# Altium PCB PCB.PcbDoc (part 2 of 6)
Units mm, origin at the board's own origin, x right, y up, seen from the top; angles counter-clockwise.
Board outline 101.6 x 101.61 mm, 4 copper layers (Top Layer, GND, POWER, Bottom Layer), stack 1.371 mm thick; 504 components, 345 nets, 1794 pads, 1471 vias.

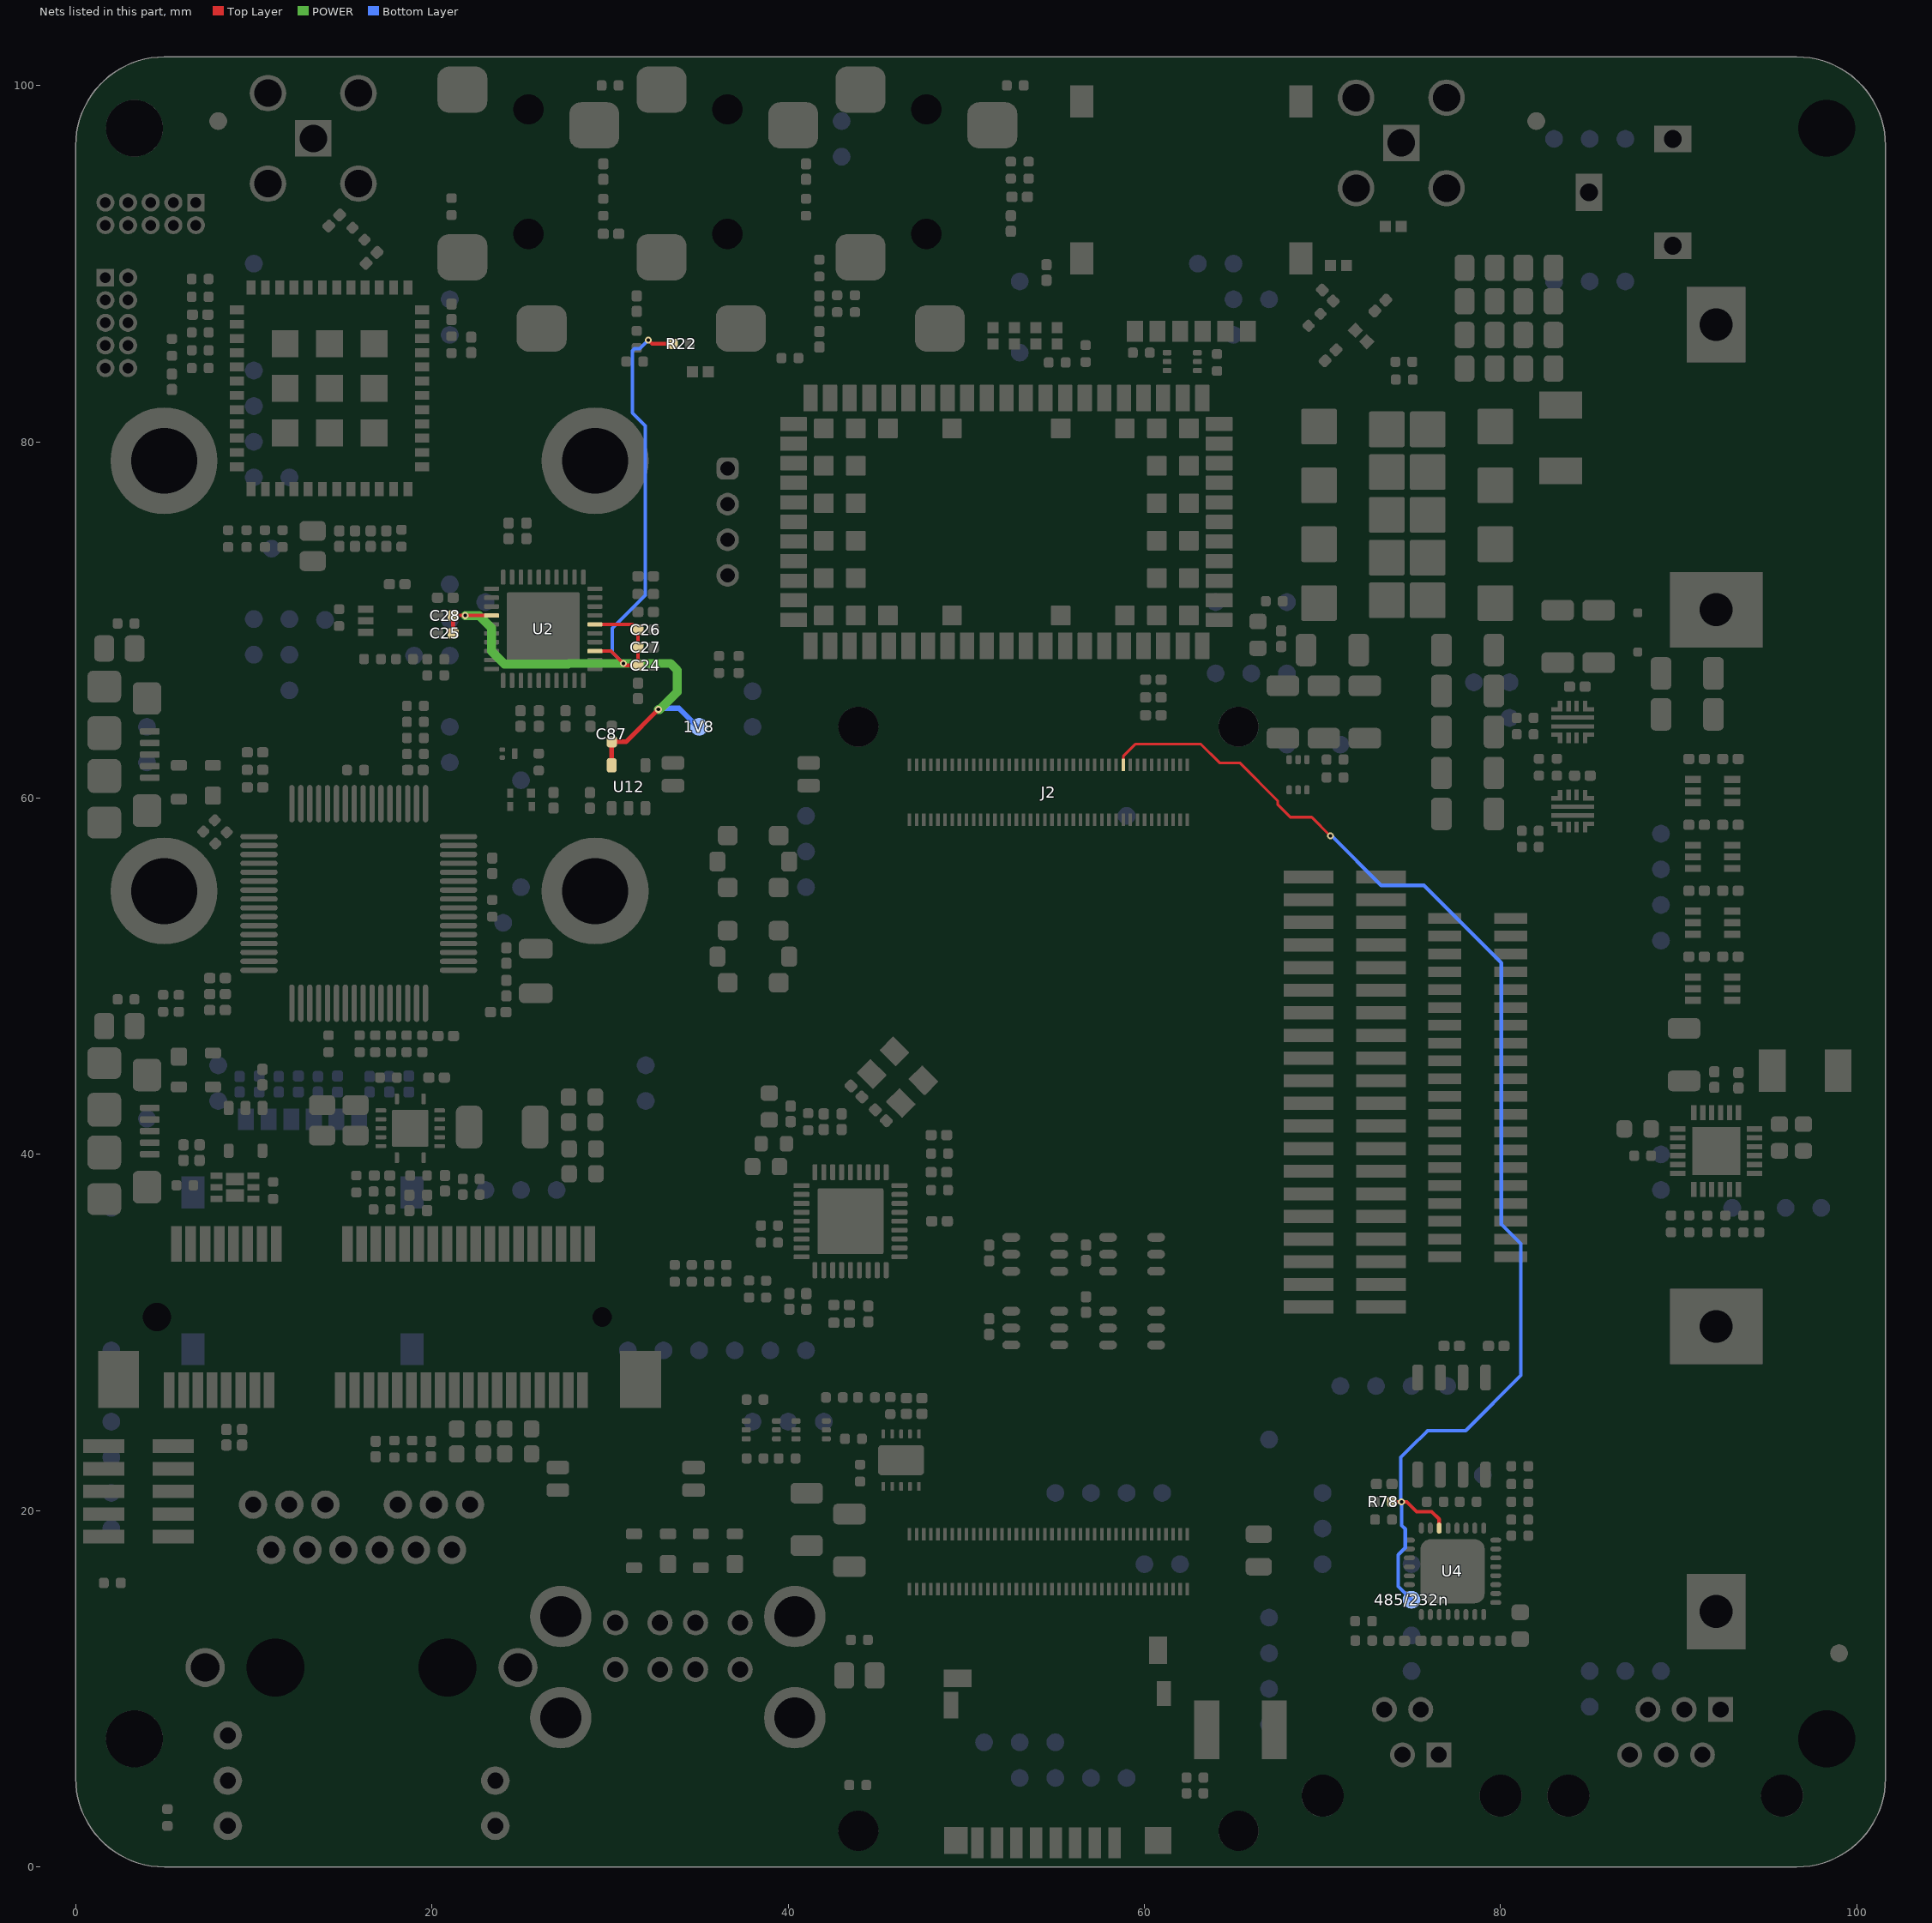
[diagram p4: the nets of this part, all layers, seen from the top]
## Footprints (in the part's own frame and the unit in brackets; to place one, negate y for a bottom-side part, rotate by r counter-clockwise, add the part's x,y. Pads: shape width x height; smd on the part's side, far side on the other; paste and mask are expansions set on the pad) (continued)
0402#3 [mm] "Chip Inductor, 2-Leads, Body  0402 (in) 1005 (mm), IPC Medium Density"
  rect 0.62x0.62 smd mask+0.05: 1(-0.45,0) 2(0.45,0)
  body extent -0.57,-0.27 0.57,0.27, height 0.41
1812 [mm] "Chip Capacitor, Body 4.5x3.2mm, IPC High Density"
  rect 1.4x3.3 smd: 1(-1.9,0) 2(1.9,0)
  body extent -2.4,-1.7 2.4,1.7, height 1.4
1759546-1 [mm]
  rect 0.6x2 smd mask+0: 1(-11.8,-4.25) 2(-11.4,3.95) 3(-11,-4.25) 4(-10.6,3.95) 5(-10.2,-4.25) 6(-9.8,3.95) 7(-9.4,-4.25) 8(-9,3.95) 9(-8.6,-4.25) 10(-8.2,3.95) 11(-7.8,-4.25) 12(-7.4,3.95) 13(-7,-4.25) 14(-6.6,3.95) 15(-6.2,-4.25) 16(-5.8,3.95) 17(-2.2,-4.25) 18(-1.8,3.95) 19(-1.4,-4.25) 20(-1,3.95) 21(-0.6,-4.25) 22(-0.2,3.95) 23(0.2,-4.25) 24(0.6,3.95) 25(1,-4.25) 26(1.4,3.95) 27(1.8,-4.25) 28(2.2,3.95) 29(2.6,-4.25) 30(3,3.95) 31(3.4,-4.25) 32(3.8,3.95) 33(4.2,-4.25) 34(4.6,3.95) 35(5,-4.25) 36(5.4,3.95) 37(5.8,-4.25) 38(6.2,3.95) 39(6.6,-4.25) 40(7,3.95) 41(7.4,-4.25) 42(7.8,3.95) 43(8.2,-4.25) 44(8.6,3.95) 45(9,-4.25) 46(9.4,3.95) 47(9.8,-4.25) 48(10.2,3.95) 49(10.6,-4.25) 50(11,3.95) 51(11.4,-4.25) 52(11.8,3.95)
  round 0 hole 1.6 unplated: MH1(-12.5,-0.15)
  round 0 hole 1.1 unplated: MH2(12.5,-0.15)
  rect 2.3x3.2 smd: MP1(-14.65,-3.65) MP2(14.65,-3.65)
  body extent -15,-4.56 15,4.7, height 9.92
9774070151R [mm]
  round 6 / inner round 4.1 / far side round 4.1 hole 3.7 paste-10 mask+0.1: 1(0,0)
  body extent -2.55,-2.55 2.55,2.55, height 7.03
61400826021 [mm] "USB 2.0 Type A Horizontal Dual Stacked"
  round 1.42 hole 0.92: 1(-3.5,7.11) 2(-1,7.11) 3(1,7.11) 4(3.5,7.11) 5(-3.5,4.49) 6(-1,4.49) 7(1,4.49) 8(3.5,4.49)
  round 3.45 hole 2.3: Shell(-6.57,1.78) Shell(-6.57,7.46) Shell(6.57,1.78) Shell(6.57,7.46)
  body extent -7.91,-8.5 7.91,8.65, height 15.93
615004143821 [mm] "Modular Jack Horizontal Plastic 4P4C Tab Up"
  rect 1.4x1.4 hole 0.9: 1(1.53,1.8)
  round 1.4 hole 0.9: 2(0.51,4.34) 3(-0.51,1.8) 4(-1.53,4.34)
  round 2.36 hole 2.36 unplated: MH1(5,-0.5) MH2(-5,-0.5)
  body extent -6.28,-6.5 6.27,6.5, height 14.55
615006138421 [mm] "Modular Jack Horizontal Plastic 6P6C Tab Up"
  rect 1.4x1.4 hole 0.9: 1(2.55,4.34)
  round 1.4 hole 0.9: 2(1.53,1.8) 3(0.51,4.34) 4(-0.51,1.8) 5(-1.53,4.34) 6(-2.55,1.8)
  round 2.36 hole 2.36 unplated: MH1(-6,-0.5) MH2(6,-0.5)
  body extent -7.19,-6.5 7.19,6.5, height 14.55
ABS07 [mm]
  rrect50% 1.1x1.9 smd: 1(-1.25,0) 2(1.25,0)
  body extent -1.65,-0.83 1.65,0.83, height 0.9
AMPHENOL_114-00841-68 [mm]
  rect 0.7x1.75 smd mask+0.05: 1(3.2,-5.888) 2(2.1,-5.888) 3(1,-5.888) 4(-0.1,-5.888) 5(-1.2,-5.888) 6(-2.3,-5.888) 7(-3.4,-5.888) 8(-4.5,-5.888)
  rect 1x1.55 smd mask+0.05: CD1(5.65,4.912)
  rect 1.55x1 smd mask+0.05: CD2(-5.602,3.337)
  rect 1.3x1.5 smd mask+0: SH1(-5.7,-5.76)
  rect 1.5x1.5 smd mask+0: SH2(5.65,-5.76)
  rect 0.8x1.4 smd mask+0.05: SH3(5.975,2.487)
  rect 0.8x1.5 smd mask+0.05: SH4(-5.975,1.837)
  body extent -6,-10.29 6,4.99, height 1.6
C&K_PTS820_NO_HOLES-1 [mm]
  rrect49% 0.89x1.12 smd: 5(-2.015,0) 6(2.015,0)
  rrect46% 1.11x1.09 smd: PAD(-1.434,-1.46) PAD(-1.434,1.46) PAD(1.434,-1.46) PAD(1.434,1.46)
  body extent -2.25,-1.45 2.25,1.45, height 2
CAP-0402#1 [mm] "Chip Capacitor, 2-Leads, Body  0402 (in) 1005 (mm), IPC Medium Density"
  rrect52% 0.63x0.58 smd: 1(-0.435,0) 2(0.435,0)
  body extent -0.5,-0.25 0.5,0.25, height 0.5
CAP-0402#2 [mm] "Chip Capacitor, 2-Leads, Body  0402 (in) 1005 (mm), IPC Medium Density"
  rrect52% 0.63x0.58 smd mask+0: 1(-0.435,0) 2(0.435,0)
  body extent -0.5,-0.25 0.5,0.25, height 0.5
CAP-0603#1 [mm] "Chip Capacitor, Body 0603 imperial,1.6x0.8mm, IPC High Density"
  rrect51% 0.87x0.97 smd: 1(-0.75,0) 2(0.75,0)
  body extent -0.8,-0.4 0.8,0.4, height 0.8
CAP-0603#2 [mm] "Chip Capacitor, Body 0603 imperial,1.6x0.8mm, IPC High Density"
  rrect51% 0.87x0.97 smd mask+0: 1(-0.75,0) 2(0.75,0)
  body extent -0.8,-0.4 0.8,0.4, height 0.8
CAP-0805#1 [mm] "Chip Capacitor, Body 0805 imperial, 2.0x1.2mm, IPC Medium Density"
  rrect45% 1.11x1.47 smd: 1(-0.85,0) 2(0.85,0)
  body extent -1,-0.62 1,0.63, height 1.25
CAP-0805#2 [mm] "Chip Capacitor, Body 0805 imperial, 2.0x1.2mm, IPC Medium Density"
  rrect45% 1.11x1.47 smd mask+0: 1(-0.85,0) 2(0.85,0)
  body extent -1,-0.62 1,0.63, height 1.25
CAP-1206#1 [mm] "Chip Capacitor, 2-Leads, 1206 (in) 3216 (mm), IPC Medium Density"
  rrect43% 1.16x1.82 smd: 1(-1.475,0) 2(1.475,0)
  body extent -1.6,-0.8 1.6,0.8, height 1.6
CAP-1206#2 [mm] "Chip Capacitor, 2-Leads, 1206 (in) 3216 (mm), IPC Medium Density"
  rrect43% 1.16x1.82 smd mask+0: 1(-1.475,0) 2(1.475,0)
  body extent -1.6,-0.8 1.6,0.8, height 1.6
CMWX1ZZABZ [mil]
  rect 31.5x19.69 smd mask+2.76: 1(-222.44,173.23) 2(-222.44,141.73) 3(-222.44,110.24) 4(-222.44,78.74) 5(-222.44,47.24) 6(-222.44,15.75) 7(-222.44,-15.75) 8(-222.44,-47.24) 9(-222.44,-78.74) 10(-222.44,-110.24) 11(-222.44,-141.73) 12(-222.44,-173.23) 25(222.44,-173.23) 26(222.44,-141.73) 27(222.44,-110.24) 28(222.44,-78.74) 29(222.44,-47.24) 30(222.44,-15.75) 31(222.44,15.75) 32(222.44,47.24) 33(222.44,78.74) 34(222.44,110.24) 35(222.44,141.73) 36(222.44,173.23)
  rect 19.69x31.5 smd mask+2.76: 13(-173.23,-204.72) 14(-141.73,-204.72) 15(-110.24,-204.72) 16(-78.74,-204.72) 17(-47.24,-204.72) 18(-15.75,-204.72) 19(15.75,-204.72) 20(47.24,-204.72) 21(78.74,-204.72) 22(110.24,-204.72) 23(141.73,-204.72) 24(173.23,-204.72) 37(173.23,204.72) 38(141.73,204.72) 39(110.24,204.72) 40(78.74,204.72) 41(47.24,204.72) 42(15.75,204.72) 43(-15.75,204.72) 44(-47.24,204.72) 45(-78.74,204.72) 46(-110.24,204.72) 47(-141.73,204.72) 48(-173.23,204.72)
  rect 59.06x59.06 smd mask+2.76: 49(-98.43,98.43) 50(0,98.43) 51(98.43,98.43) 52(-98.43,0) 53(0,0) 54(98.43,0) 55(-98.43,-98.43) 56(0,-98.43) 57(98.43,-98.43)
  body extent -244,-225 248,231, height 69
CRYSTAL3.2X2.5 [mm]
  rrect10% 1.3x1.1 smd: 1(-1.15,-0.9) 2(1.15,-0.9) 3(1.15,0.9) 4(-1.15,0.9)
  body extent -1.65,-1.14 1.52,1.27, height 0.6
CTS-218-2LPST_V [mm] "SMD, 4-Leads, Body 5.8x3.71mm, Pitch 1.27mm"
  rrect50% 1.27x0.76 smd: 1(-3.81,0.635) 2(-3.81,-0.635) 3(3.81,-0.635) 4(3.81,0.635)
  body extent -2.9,-1.86 2.9,1.86, height 2.65
CUI-PJ-102A_V [mm] "THD, 3-Leads, Body 14.4x9mm, Pitch 3mm"
  rect 2.1x1.5 hole 1 square: 1(0.2,-6.5) 2(0.2,-0.5)
  rect 1.5x2.1 hole 1 square: 3(-4.5,-3.5)
  body extent -4.7,-7.2 4.7,7.2, height 11.5
DF40HC(3.5)-80DS-0.4V(51)-Footprint-1 [mm]
  rect 0.2x0.7 smd: 1(-7.8,1.54) 2(-7.8,-1.54) 3(-7.4,1.54) 4(-7.4,-1.54) 5(-7,1.54) 6(-7,-1.54) 7(-6.6,1.54) 8(-6.6,-1.54) 9(-6.2,1.54) 10(-6.2,-1.54) 11(-5.8,1.54) 12(-5.8,-1.54) 13(-5.4,1.54) 14(-5.4,-1.54) 15(-5,1.54) 16(-5,-1.54) 17(-4.6,1.54) 18(-4.6,-1.54) 19(-4.2,1.54) 20(-4.2,-1.54) 21(-3.8,1.54) 22(-3.8,-1.54) 23(-3.4,1.54) 24(-3.4,-1.54) 25(-3,1.54) 26(-3,-1.54) 27(-2.6,1.54) 28(-2.6,-1.54) 29(-2.2,1.54) 30(-2.2,-1.54) 31(-1.8,1.54) 32(-1.8,-1.54) 33(-1.4,1.54) 34(-1.4,-1.54) 35(-1,1.54) 36(-1,-1.54) 37(-0.6,1.54) 38(-0.6,-1.54) 39(-0.2,1.54) 40(-0.2,-1.54) 41(0.2,1.54) 42(0.2,-1.54) 43(0.6,1.54) 44(0.6,-1.54) 45(1,1.54) 46(1,-1.54) 47(1.4,1.54) 48(1.4,-1.54) 49(1.8,1.54) 50(1.8,-1.54) 51(2.2,1.54) 52(2.2,-1.54) 53(2.6,1.54) 54(2.6,-1.54) 55(3,1.54) 56(3,-1.54) 57(3.4,1.54) 58(3.4,-1.54) 59(3.8,1.54) 60(3.8,-1.54) 61(4.2,1.54) 62(4.2,-1.54) 63(4.6,1.54) 64(4.6,-1.54) 65(5,1.54) 66(5,-1.54) 67(5.4,1.54) 68(5.4,-1.54) 69(5.8,1.54) 70(5.8,-1.54) 71(6.2,1.54) 72(6.2,-1.54) 73(6.6,1.54) 74(6.6,-1.54) 75(7,1.54) 76(7,-1.54) 77(7.4,1.54) 78(7.4,-1.54) 79(7.8,1.54) 80(7.8,-1.54)
  body extent -9.32,-1.69 9.28,1.69, height 3.4
DFN120P120X89-4M [mm] "DFN, 4-Leads, Body 1,60x1,20mm, Pitch 1,20mm, IPC Low Density"
  rect 0.45x0.5 smd mask+0.04: 1(-0.555,-0.375)
  rect 0.35x0.5 smd mask+0.04: 2(0.605,-0.375) 3(0.605,0.375) 4(-0.605,0.375)
  body extent -0.8,-0.6 0.8,0.6, height 0.9
"Fiducial mark 1mm with circle-Footprint-1" [mm]
  round 1 smd paste-10 mask+0.5: 1(0,0)
  Top Layer pour cut-out: 0,1 0.383,0.924 0.707,0.707 0.924,0.383 1,0 1,0 0.924,-0.383 0.707,-0.707 0.383,-0.924 0,-1 0,-1 -0.383,-0.924 -0.707,-0.707 -0.924,-0.383 -1,0 -1,0 -0.924,0.383 -0.707,0.707 -0.383,0.924 0,1
FTSH-105-01-F-DV-Footprint-1 [mm]
  rect 0.76x2.3 smd: 1(-2.54,-1.95) 2(-2.54,1.95) 3(-1.27,-1.95) 4(-1.27,1.95) 5(0,-1.95) 6(0,1.95) 7(1.27,-1.95) 8(1.27,1.95) 9(2.54,-1.95) 10(2.54,1.95)
  body extent -3.17,-2.92 3.17,2.92, height 5.98
FW-20-05-G-D-254-150-Footprint-1 [mil]
  rect 110x29 smd: 1(-80,475) 2(80,475) 3(-80,425) 4(80,425) 5(-80,375) 6(80,375) 7(-80,325) 8(80,325) 9(-80,275) 10(80,275) 11(-80,225) 12(80,225) 13(-80,175) 14(80,175) 15(-80,125) 16(80,125) 17(-80,75) 18(80,75) 19(-80,25) 20(80,25) 21(-80,-25) 22(80,-25) 23(-80,-75) 24(80,-75) 25(-80,-125) 26(80,-125) 27(-80,-175) 28(80,-175) 29(-80,-225) 30(80,-225) 31(-80,-275) 32(80,-275) 33(-80,-325) 34(80,-325) 35(-80,-375) 36(80,-375) 37(-80,-425) 38(80,-425) 39(-80,-475) 40(80,-475)
  body extent -115,-500 115,500, height 388
HW4-2.0 [mm]
  rrect50% 1.23x1.23 hole 0.8: 1(-3,0)
  round 1.27 / inner round 1.524 / far side round 1.27 hole 0.8: 2(-1,0) 3(1,0) 4(3,0)
  body extent -5.02,-3.22 5.02,2.03, height 8.09
L-0603 [mm] "Chip Inductor - Body 0603 imperial,1.6x0.8mm, IPC High Density"
  rrect51% 0.75x0.87 smd: 1(-0.71,0) 2(0.71,0)
  body extent -0.8,-0.4 0.8,0.4, height 0.8
LGA18C100P6X4_1200X1200X360 [mm] "LGA, 18-Leads, Body 12.00x12.00mmx3.60mm, Pitch 1.00mm"
  rrect10% 2x2 smd: 1(-4.95,4.95) 2(-4.95,1.65) 3(-4.95,-1.65) 4(-4.95,-4.95) 5(4.95,-4.95) 8(4.95,4.95) GND(-1.15,-4.8) GND(-1.15,-2.4) GND(-1.15,0) GND(-1.15,2.4) GND(-1.15,4.8) GND(1.15,-4.8) GND(1.15,-2.4) GND(1.15,0) GND(1.15,2.4) GND(1.15,4.8) GND(4.95,-1.65) GND(4.95,1.65)
  body extent -6.05,-6.05 6.05,6.05, height 3.6
MCHP-QFN-36_V [mm] "QFN, 36-Leads, Body 6.00x6.00mm, Pitch 0.50mm, Thermal Pad 3.70x3.70mm"
  rrect50% 0.9x0.28 smd mask+0.03: 1(-2.75,2) 2(-2.75,1.5) 3(-2.75,1) 4(-2.75,0.5) 5(-2.75,0) 6(-2.75,-0.5) 7(-2.75,-1) 8(-2.75,-1.5) 9(-2.75,-2) 19(2.75,-2) 20(2.75,-1.5) 21(2.75,-1) 22(2.75,-0.5) 23(2.75,0) 24(2.75,0.5) 25(2.75,1) 26(2.75,1.5) 27(2.75,2)
  rrect50% 0.28x0.9 smd mask+0.03: 10(-2,-2.75) 11(-1.5,-2.75) 12(-1,-2.75) 13(-0.5,-2.75) 14(0,-2.75) 15(0.5,-2.75) 16(1,-2.75) 17(1.5,-2.75) 18(2,-2.75) 28(2,2.75) 29(1.5,2.75) 30(1,2.75) 31(0.5,2.75) 32(0,2.75) 33(-0.5,2.75) 34(-1,2.75) 35(-1.5,2.75) 36(-2,2.75)
  rrect5% 3.7x3.7 smd paste-4 mask+0.03: 37(0,0)
  body extent -3.05,-3.05 3.05,3.05, height 1
MOLX-731000114_V [mm] "Connector, 5-Leads, Body 14.8x6.35mm, Pitch 2.54mm"
  rect 2.05x2.05 hole 1.54: 1(0,0)
  round 2.05 hole 1.54: 2(-2.54,2.54) 3(-2.54,-2.54) 4(2.54,-2.54) 5(2.54,2.54)
  body extent -11.62,-3.17 3.18,3.18, height 9.57
PINHEAD_2X05_127 [mil]
  rect 38.73x38.73 / inner rect 38.74x38.74 / far side rect 38.73x38.73 hole 23.62: 1(-25,100)
  round 40 hole 23.62: 2(25,100) 3(-25,50) 4(25,50) 5(-25,0) 6(25,0) 7(-25,-50) 8(25,-50) 9(-25,-100) 10(25,-100)
PQFN50P300X300X55_HS-21L [mm] "PQFN, 20-Leads, Body 3.00x3.00mm, Pitch 0.50mm, Thermal Pad 1.69x2.59mm, IPC High Density"
  rrect50% 0.2x0.5 smd: 1(-1,-1.475) 2(-0.5,-1.475) 3(0,-1.475) 4(0.5,-1.475) 5(1,-1.475) 6(1,1.475) 7(0.5,1.475) 8(0,1.475) 9(-0.5,1.475) 10(-1,1.475)
  rrect25% 2.59x1.69 smd: 11(0,0)
  body extent -1.5,-1.5 1.5,1.5, height 0.55
QFN50P200X200X100-16N [mm] "QFN, 16-Leads, Body 2,00x2,00mm, Pitch 0,50mm, IPC Medium Density"
  rect 0.6x0.25 smd mask+0.03: 1(-0.889,0.7) 2(-0.9,0.225) 3(-0.9,-0.225) 4(-0.889,-0.7) 7(0.889,-0.7) 8(0.9,-0.225) 9(0.9,0.225) 10(0.889,0.7)
  rect 0.25x0.6 smd mask+0.03: 1(-0.714,0.9) 4(-0.714,-0.9) 7(0.714,-0.9) 10(0.714,0.9)
  rect 0.25x2.4 smd mask+0.03: 5(-0.25,0) 6(0.25,0)
  body extent -1.05,-1.05 1.05,1.05, height 1
QFN50P500X500X100_HS-33N [mm] "QFN, 32-Leads, Body 5,00x5,00mm, Pitch 0,50mm, Thermal Pad 3,65x3,65mm, IPC Medium Density"
  oval 0.625x0.275 smd: 1(-2.425,1.75) 2(-2.425,1.25) 3(-2.425,0.75) 4(-2.425,0.25) 5(-2.425,-0.25) 6(-2.425,-0.75) 7(-2.425,-1.25) 8(-2.425,-1.75) 17(2.425,-1.75) 18(2.425,-1.25) 19(2.425,-0.75) 20(2.425,-0.25) 21(2.425,0.25) 22(2.425,0.75) 23(2.425,1.25) 24(2.425,1.75)
  oval 0.275x0.625 smd: 9(-1.75,-2.425) 10(-1.25,-2.425) 11(-0.75,-2.425) 12(-0.25,-2.425) 13(0.25,-2.425) 14(0.75,-2.425) 15(1.25,-2.425) 16(1.75,-2.425) 25(1.75,2.425) 26(1.25,2.425) 27(0.75,2.425) 28(0.25,2.425) 29(-0.25,2.425) 30(-0.75,2.425) 31(-1.25,2.425) 32(-1.75,2.425)
  rrect30% 3.6x3.6 smd paste-6: 33(0,0)
  body extent -2.5,-2.5 2.5,2.5, height 1.02
QFN127P600-8N [mm]
  rrect50% 0.85x0.25 smd mask+0.05: 1(-2.9,2.25) 2(-2.9,1.75) 3(-2.9,1.25) 4(-2.9,0.75) 5(-2.9,0.25) 6(-2.9,-0.25) 7(-2.9,-0.75) 8(-2.9,-1.25) 9(-2.9,-1.75) 10(-2.9,-2.25) 21(2.9,-2.25) 22(2.9,-1.75) 23(2.9,-1.25) 24(2.9,-0.75) 25(2.9,-0.25) 26(2.9,0.25) 27(2.9,0.75) 28(2.9,1.25) 29(2.9,1.75) 30(2.9,2.25)
  rrect50% 0.25x0.85 smd mask+0.05: 11(-2.25,-2.9) 12(-1.75,-2.9) 13(-1.25,-2.9) 14(-0.75,-2.9) 15(-0.25,-2.9) 16(0.25,-2.9) 17(0.75,-2.9) 18(1.25,-2.9) 19(1.75,-2.9) 20(2.25,-2.9) 31(2.25,2.9) 32(1.75,2.9) 33(1.25,2.9) 34(0.75,2.9) 35(0.25,2.9) 36(-0.25,2.9) 37(-0.75,2.9) 38(-1.25,2.9) 39(-1.75,2.9) 40(-2.25,2.9)
  rrect5% 4.1x4.1 smd paste-5 mask+0.05: 41(0,0)
  body extent -3,-3 3,3, height 1
RES-0402#1 [mm] "Chip Resistor, 2-Leads, Body  0402 (in) 1005 (mm), IPC Medium Density"
  rrect51% 0.55x0.58 smd: 1(-0.475,0) 2(0.475,0)
  body extent -0.5,-0.25 0.5,0.25, height 0.34
RES-0402#2 [mm] "Chip Resistor, 2-Leads, Body  0402 (in) 1005 (mm), IPC Medium Density"
  rrect51% 0.55x0.58 smd mask+0: 1(-0.475,0) 2(0.475,0)
  body extent -0.5,-0.25 0.5,0.25, height 0.34
RES-0402#3 [mm] "Chip Resistor, 2-Leads, Body  0402 (in) 1005 (mm), IPC Medium Density"
  rrect51% 0.55x0.58 smd mask+0: 1(-0.475,0)
  rrect51% 0.55x0.58 smd: 2(0.475,0)
  body extent -0.5,-0.25 0.5,0.25, height 0.34
RES-0805 [mm] "Chip Resistor - Body 0805 imperial, 2.0x1.2mm, IPC Medium Density"
  rrect51% 0.99x1.47 smd paste-1.47: 1(-0.915,0) 2(0.915,0)
  body extent -1,-0.62 1,0.63, height 0.58
RHL0014A_V [mm] "QFN, 14-Leads, Body 3.5x3.5mm, Pitch 0.5mm, Thermal Pad 2.05x2.05mm, TI Recommended"
  rrect42% 0.24x0.6 smd: 1(-0.75,1.65) 7(-0.75,-1.65) 8(0.75,-1.65) 14(0.75,1.65)
  rrect42% 0.6x0.24 smd: 2(-1.65,1) 3(-1.65,0.5) 4(-1.65,0) 5(-1.65,-0.5) 6(-1.65,-1) 9(1.65,-1) 10(1.65,-0.5) 11(1.65,0) 12(1.65,0.5) 13(1.65,1)
  rrect5% 2.05x2.05 smd paste-1.025: 15(0,0)
  Top Layer region: -0.375,0.762 0.375,0.762 0.375,1.75 0.175,1.75 0.175,1.425 -0.175,1.425 -0.175,1.75 -0.375,1.75
  Top Layer region: -0.375,0 0.375,0 0.375,-1.75 0.175,-1.75 0.175,-1.425 -0.175,-1.425 -0.175,-1.75 -0.375,-1.75
  body extent -1.68,-1.83 1.68,1.82, height 1
SARA-96 [mil]
  rrect10% 31.5x59.06 smd: 1(-433.07,-273.62) 2(-389.76,-273.62) 3(-346.46,-273.62) 4(-303.15,-273.62) 5(-259.84,-273.62) 6(-216.54,-273.62) 7(-173.23,-273.62) 8(-129.92,-273.62) 9(-86.61,-273.62) 10(-43.31,-273.62) 11(0,-273.62) 12(43.31,-273.62) 13(86.61,-273.62) 14(129.92,-273.62) 15(173.23,-273.62) 16(216.54,-273.62) 17(259.84,-273.62) 18(303.15,-273.62) 19(346.46,-273.62) 20(389.76,-273.62) 21(433.07,-273.62) 33(433.07,273.62) 34(389.76,273.62) 35(346.46,273.62) 36(303.15,273.62) 37(259.84,273.62) 38(216.54,273.62) 39(173.23,273.62) 40(129.92,273.62) 41(86.61,273.62) 42(43.31,273.62) 43(0,273.62) 44(-43.31,273.62) 45(-86.61,273.62) 46(-129.92,273.62) 47(-173.23,273.62) 48(-216.54,273.62) 49(-259.84,273.62) 50(-303.15,273.62) 51(-346.46,273.62) 52(-389.76,273.62) 53(-433.07,273.62)
  rrect10% 59.06x31.5 smd: 22(470.47,-216.54) 23(470.47,-173.23) 24(470.47,-129.92) 25(470.47,-86.61) 26(470.47,-43.31) 27(470.47,0) 28(470.47,43.31) 29(470.47,86.61) 30(470.47,129.92) 31(470.47,173.23) 32(470.47,216.54) 54(-470.47,216.54) 55(-470.47,173.23) 56(-470.47,129.92) 57(-470.47,86.61) 58(-470.47,43.31) 59(-470.47,0) 60(-470.47,-43.31) 61(-470.47,-86.61) 62(-470.47,-129.92) 63(-470.47,-173.23) 64(-470.47,-216.54)
  rrect10% 43.31x43.31 smd: 65(-403.54,-206.69) 66(-403.54,-124.02) 67(-403.54,-41.34) 68(-403.54,41.34) 69(-403.54,124.02) 70(-403.54,206.69) 71(-332.68,-206.69) 72(-332.68,-124.02) 73(-332.68,-41.34) 74(-332.68,41.34) 75(-332.68,124.02) 76(-332.68,206.69) 77(-261.81,-206.69) 78(-261.81,206.69) 79(-120.08,-206.69) 80(-120.08,206.69) 81(120.08,-206.69) 82(120.08,206.69) 83(261.81,-206.69) 84(261.81,206.69) 85(332.68,-206.69) 86(332.68,-124.02) 87(332.68,-41.34) 88(332.68,41.34) 89(332.68,124.02) 90(332.68,206.69) 91(403.54,-206.69) 92(403.54,-124.02) 93(403.54,-41.34) 94(403.54,41.34) 95(403.54,124.02) 96(403.54,206.69)
  body extent -512,-315 512,315, height 103
SC70-5 [mm] "SC70-5/SOT353, 5-Leads, Body 2.00x2.10mm, Pitch 0.65mm, IPC Medium Density"
  rect 0.85x0.4 smd mask+0.05: 1(-1.1,0.65) 2(-1.1,0) 3(-1.1,-0.65) 4(1.1,-0.65) 5(1.1,0.65)
  body extent -1.2,-1.08 1.2,1.08, height 1.1
sc70-6 [mm]
  rrect10% 0.9x0.4 smd mask+0.05: 1(-1.1,0.65) 2(-1.1,0) 3(-1.1,-0.65) 4(1.1,-0.65) 5(1.1,0) 6(1.1,0.65)
  body extent -1.05,-1 1.05,1, height 0.93
SIM8060-6-0-14-00-A-Footprint-1 [mm]
  rect 0.9x1.2 smd: C1(-3.17,7.32) C2(-0.63,7.32) C3(1.91,7.32) C5(-1.9,7.32) C6(0.64,7.32) C7(3.18,7.32)
  rect 1.3x1.8 smd: G1(-6.15,3.22) G2(6.15,3.22) G3(-6.15,-5.58) G4(6.15,-5.58)
  silkscreen extent -3.3,8.2 -3.1,8.4, body extent -6.67,-7.92 6.67,7.83, height 1.53
SJ-3524-SMT-TR-Footprint-1 [mm]
  rrect50% 2.6x2.8 smd: 1(-4.59,-3.7) 2(-2.59,3.7) 3(4.81,-3.7) 4(8.81,0.75)
  round 0 hole 1.7 unplated: MH1(-3.49,0) MH2(3.51,0)
  body extent -9.49,-4.5 9.51,4.5, height 5.1
SOD323 [mm] "Molded Diode, 2-Leads, Body 1,70x1,25mm, IPC High Density"
  rrect50% 0.5x0.5 smd: 1(-1.1,0) 2(1.1,0)
  body extent -1.12,-0.67 1.12,0.67, height 1.1
SON65P205X205X75-8N-MWSD [mm]
  rect 0.37x0.67 smd mask+0.025: A(0.65,1.04) D(-0.65,1.04) G(0,-1.04) K(0.65,-1.04) NC(0,1.04) S(-0.65,-1.04)
  rect 0.7x1 smd mask+0.025: D2(-0.467,0) K2(0.467,0)
  body extent -1,-1 1,1, height 0.75
SOT25 [mil]
  rrect50% 21.65x31.5 smd: 1(-37.4,-47.24) 2(0,-47.24) 3(37.4,-47.24) 4(37.4,47.24) 5(-37.4,47.24)
  body extent -59,-44 59,50, height 43
SOT190P230X110-4N [mm]
  rrect33% 1.01x0.91 smd paste+0 mask+0: 1(-0.75,-0.955)
  rrect49% 0.61x0.91 smd paste+0 mask+0: 2(0.95,-0.955) 3(0.95,0.955) 4(-0.95,0.955)
  body extent -1.45,-1.15 1.45,1.15, height 1
SOT883 [mm]
  rrect50% 0.3x0.25 smd mask+0: 1(-0.35,-0.225) 2(-0.35,0.225)
  rrect25% 0.3x0.6 smd mask+0.05: 3(0.35,0)
  body extent -0.51,-0.31 0.51,0.31, height 0.5
SOTFL50P158X60-6N [mm] "SOTFL, 6-Leads, Body 1,55x1,58mm, Pitch 0,50mm, IPC Medium Density"
  rrect50% 0.5x0.3 smd mask+0.025: 1(-0.85,0.5) 2(-0.85,0) 3(-0.85,-0.5) 4(0.85,-0.5) 5(0.85,0) 6(0.85,0.5)
  body extent -0.79,-0.8 0.79,0.8, height 0.6
SRP4020#1 [mm]
  rect 1.5x2.4 smd: 1(-1.85,0) 2(1.85,0)
  body extent -2.15,-2 2.15,2, height 1.9
SRP4020#2 [mm]
  rrect50% 1.5x2.4 smd: 1(-1.85,0) 2(1.85,0)
  body extent -2.7,-2.25 2.7,2.25, height 0.25
STM-LQFP64_M [mm] "Thin QFP, 64-Leads, Body 10x10mm, Pitch 0.5mm, IPC Low Density"
  oval 2.1x0.3 smd: 1(-5.6,3.75) 2(-5.6,3.25) 3(-5.6,2.75) 4(-5.6,2.25) 5(-5.6,1.75) 6(-5.6,1.25) 7(-5.6,0.75) 8(-5.6,0.25) 9(-5.6,-0.25) 10(-5.6,-0.75) 11(-5.6,-1.25) 12(-5.6,-1.75) 13(-5.6,-2.25) 14(-5.6,-2.75) 15(-5.6,-3.25) 16(-5.6,-3.75) 33(5.6,-3.75) 34(5.6,-3.25) 35(5.6,-2.75) 36(5.6,-2.25) 37(5.6,-1.75) 38(5.6,-1.25) 39(5.6,-0.75) 40(5.6,-0.25) 41(5.6,0.25) 42(5.6,0.75) 43(5.6,1.25) 44(5.6,1.75) 45(5.6,2.25) 46(5.6,2.75) 47(5.6,3.25) 48(5.6,3.75)
  oval 0.3x2.1 smd: 17(-3.75,-5.6) 18(-3.25,-5.6) 19(-2.75,-5.6) 20(-2.25,-5.6) 21(-1.75,-5.6) 22(-1.25,-5.6) 23(-0.75,-5.6) 24(-0.25,-5.6) 25(0.25,-5.6) 26(0.75,-5.6) 27(1.25,-5.6) 28(1.75,-5.6) 29(2.25,-5.6) 30(2.75,-5.6) 31(3.25,-5.6) 32(3.75,-5.6) 49(3.75,5.6) 50(3.25,5.6) 51(2.75,5.6) 52(2.25,5.6) 53(1.75,5.6) 54(1.25,5.6) 55(0.75,5.6) 56(0.25,5.6) 57(-0.25,5.6) 58(-0.75,5.6) 59(-1.25,5.6) 60(-1.75,5.6) 61(-2.25,5.6) 62(-2.75,5.6) 63(-3.25,5.6) 64(-3.75,5.6)
  body extent -6,-6 6,6, height 1.6
TJA1049T_3J-Footprint-1 [mm]
  rrect50% 1.45x0.6 smd: 1(-2.725,1.905) 2(-2.725,0.635) 3(-2.725,-0.635) 4(-2.725,-1.905) 5(2.725,-1.905) 6(2.725,-0.635) 7(2.725,0.635) 8(2.725,1.905)
  silkscreen extent -1.14,1.53 -0.89,1.78, body extent -3,-2.5 3,2.5, height 1.75
TP-1.00MM#1 [mm]
  rrect100% 1x1 smd paste-2.54: X(0,0)
TP-1.00MM#2 [mm]
  rrect100% 1x1 smd paste-2.54: X(0.486,0)
TP-1.00MM#3 [mm]
  rrect100% 1x1 smd paste-2.54: X(-0.051,0.686)
TP-1.00MM#4 [mm]
  rrect100% 1x1 smd paste-2.54: X(0,-0.588)
TP-1.00MM#5 [mm]
  rrect100% 1x1 smd paste-2.54: X(-0.711,-1.041)
TP-1.00MM#6 [mm]
  rrect100% 1x1 smd paste-2.54: X(-1.168,-6.533)
TP-1.00MM#7 [mm]
  rrect100% 1x1 smd paste-2.54: X(0.813,-7.379)
TP-1.00MM#8 [mm]
  rrect100% 1x1 smd paste-2.54: X(0,-8.395)
TP-1.00MM#9 [mm]
  rrect100% 1x1 smd paste-2.54: X(0,1.27)
"TRJK0071AWNL -Footprint-2" [mm]
  round 1.6 hole 0.9: 1(5.075,0) 2(3.045,0) 3(1.015,0) 4(-1.015,0) 5(-3.045,0) 6(-5.075,0) 7(6.09,2.54) 8(4.06,2.54) 9(2.03,2.54) 10(-2.03,2.54) 11(-4.06,2.54) 12(-6.09,2.54) 13(7.51,-12.95) 14(7.51,-15.49) 15(-7.51,-10.41) 16(-7.51,-12.95) 17(-7.51,-15.49)
  round 2.2 hole 1.6: SH1(-8.78,-6.6) SH2(8.78,-6.6)
  round 0 hole 3.25 unplated: SHNP1(-4.825,-6.6) SHNP2(4.825,-6.6)
  body extent -10.45,-19.78 10.5,4.35, height 12.89
TSOP95P280X110-6N [mm] "TSOP, 6-Leads, Body 2,90x1,50mm, Pitch 0,95mm, IPC Medium Density"
  oval 1x0.5 smd: 1(-1.35,0.95) 2(-1.35,0) 3(-1.35,-0.95) 4(1.35,-0.95) 5(1.35,0) 6(1.35,0.95)
  body extent -1.5,-1.55 1.5,1.55, height 1.1
VQFN24 [mm]
  rect 0.3x0.85 smd mask+0.02: 1(1.25,2.155) 2(0.75,2.155) 3(0.25,2.155) 4(-0.25,2.155) 5(-0.75,2.155) 6(-1.25,2.155) 13(-1.25,-2.155) 14(-0.75,-2.155) 15(-0.25,-2.155) 16(0.25,-2.155) 17(0.75,-2.155) 18(1.25,-2.155)
  rect 0.85x0.3 smd mask+0.02: 7(-2.155,1.25) 8(-2.155,0.75) 9(-2.155,0.25) 10(-2.155,-0.25) 11(-2.155,-0.75) 12(-2.155,-1.25) 19(2.155,-1.25) 20(2.155,-0.75) 21(2.155,-0.25) 22(2.155,0.25) 23(2.155,0.75) 24(2.155,1.25)
  rect 2.7x2.7 smd paste-5 mask+0.05: EXP(0,0)
  silkscreen extent 1.95,1.98 2.15,2.18, body extent -2.05,-2.05 2.05,2.05, height 1
ZX62-AB-5PA#1 [mm]
  rrect49% 0.37x1.11 smd paste+0 mask+0: 1(-1.3,2.56) 2(-0.65,2.56) 3(0,2.56) 4(0.65,2.56) 5(1.3,2.56)
  rrect37% 1.825x1.6 smd paste+0 mask+0: M1(-3.147,2.4) M4(3.147,2.4)
  rrect37% 1.78x1.9 smd paste+0 mask+0: M2(-3.82,0) M3(3.82,0)
  rrect37% 1.9x1.9 smd paste+0 mask+0: M5(-1.2,0) M6(1.2,0)
  body extent -4.4,-2.75 4.4,2.85, height 2.75
ZX62-AB-5PA#2 [mm]
  rrect49% 0.37x1.11 smd paste+0: 1(-1.3,2.56) 2(-0.65,2.56) 3(0,2.56)
  rrect49% 0.37x1.11 smd: 4(0.65,2.56) 5(1.3,2.56)
  rrect37% 1.825x1.6 smd paste+0: M1(-3.148,2.4) M4(3.148,2.4)
  rrect37% 1.78x1.9 smd paste+0: M2(-3.82,0) M3(3.82,0)
  rrect37% 1.9x1.9 smd paste+0: M5(-1.2,0) M6(1.2,0)
  body extent -4.4,-2.75 4.4,2.85, height 2.75

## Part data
1V8 3V3_1 3V3_2 3V3_DBG 3V3_PCIE 3V3_PCIE_1 3V3_PCIE_2 3V8 3V8_2 3V8_3 5V 5V_1 5V_2 12MHz_CLK 485/232n A AUDIO_MCLK AUDIO_RST B BAT BAT_GND CAN0_RX CAN0_TX CAN1_RX CAN1_TX CANH CANL CS_AIN2A CS_AIN2B CS_AIN3A CS_AIN3B DBG_3V3 DBG_BOOT DBG_GND DBG_SWCLK DBG_SWDIO DGB_RST EN_485 EN_CAN ETH_L1 ETH_L2 GND_3V3_1 GND_3V3_2 GND_3V8_1 GND_3V8_2 GND_3V8_3 H/Fn HUB_EN0 HUB_EN1 HUB_EN2 HUB_SCL HUB_SDA I2C1_SCL I2C1_SDA I2C2_SCL I2C2_SDA I2S_CK I2S_SDI I2S_SDO I2S_WS INT_BQ JTAG_GND JTAG_RST JTAG_SCK JTAG_SWD JTAG_SWO JTAG_TDI LoRa_3V3 LoRa_GND LORA_IRQ LORA_RST LoRa_SWCLK LoRa_SWDIO LORA_VDD_TCX0 MCLK_EN MDTR PCIE_CLKREQ PWR_GND1 PWR_GND2 PWR_GND3 PWR_IN PWR_IN_1 PWR_IN_2 PWR_ON RST SDC_CD SDC_CLK SDC_CMD SDC_D0 SDC_D1 SDC_D2 SDC_D3 SERIAL0_CTS SERIAL0_RTS SERIAL0_RX SERIAL0_TX SERIAL1_CTS SERIAL1_RTS SERIAL1_RX SERIAL1_TX SERIAL2_RX SERIAL2_TX SIM_DET SIM_IO SIM_SCLK SIM_SRST SIM_SSW SIM_SVCC STM_BOOT0 USB0_DN USB0_DP USB1_DN USB1_DP USB_FS_DN USB_FS_DP USB_FS_ID USB_FS_VBUS USB_H0_DN USB_H0_DP USB_H1_DN USB_H1_DP USB_H2_DN USB_H2_DP USB_H3_DN USB_H3_DP Y Z: library part UT0013-A.2, "Test point 1.00mm"
5V_DBG SERIAL3_RX SERIAL3_TX: library part UT0013-A.1, "Test point 1.00mm"
C1 C61 C62 C78 C79 C141 C142 C143 C144 C145 C146 C148 C149 C150 C151: library part C0062-A.9, "CAP CHIP 1206 100UF 10V X5R 20%", Case Code (Imperial)=0805, Case Code (Metric)=2012, Dielectric=X5R, Manufacturer=Samsung, Package=1206, Tolerance=20%, Voltage=10V
C2 C76 C77 C92: library part C0047-A.12, "CAP CHIP 0603 10uF 25V X5R 20%", Case Code (Imperial)=0603, Case Code (Metric)=1608, Dielectric=X5R, Manufacturer=Murata, Manufacturer 2=Samsung, Manufacturer Part Number 2=CL10A226MPCNUBE, Part Number=C1608X5R1A226MT000N, Tolerance=20%, Voltage=25V
C3 C7 C10 C13 C14 C15 C16 C17 C18 C19 C20 C21 C25 C26 C27 C29 C30 C32 C35 C36 C37 C43 C48 C51 C52 C53 C54 C55 C56 C58 C59 C60 C63 C67 C69 C81 C89 C93 C98 C99 C100 C101 C102 C103 C105 C109 C110 C113 C114 C115 C134 C135 C136 C137 C138 C139 C152: library part C0012-A.9, "CAP CHIP 0402 100nF 16V X7R 10%", Case Code (Imperial)=0402, Case Code (Metric)=1005, Dielectric=X7R, Manufacturer=KEMET, Manufacturer 2=AVX, Manufacturer Part Number 2=0402YC104KAT2A, Tolerance=10%, Voltage=16V
C4 C34 C82 C127: library part C0009-A.9, "CAP CHIP 0402 10nF 50V X7R 10%", Case Code (Imperial)=0402, Case Code (Metric)=1005, Dielectric=X7R, Manufacturer=KEMET, Manufacturer 2=AVX, Manufacturer Part Number 2=4025C103KAT2A, Tolerance=10%, Voltage=50V
C5: library part C0032-A.7, "CAP CHIP 0402 68pF C0G 50V 5%", Case Code (Imperial)=0402, Case Code (Metric)=1005, Dielectric=C0G, Manufacturer=AVX, Tolerance=5%, Voltage=50V
C6 C8 C90 C91: library part C0025-A.9, "CAP CHIP 0402 15PF 50V C0G 5%", Case Code (Imperial)=0402, Case Code (Metric)=1005, Dielectric=C0G, Manufacturer=Murata, Tolerance=5%, Voltage=50V
C9: library part C0034-A.9, "CAP CHIP 0402 33PF 50V C0G 5%", Case Code (Imperial)=0402, Case Code (Metric)=1005, Dielectric=C0G, Manufacturer=Murata, Tolerance=5%, Voltage=50V
C11 C24 C28 C31 C33 C38 C41 C42 C47 C49 C87 C88 C94 C95 C96 C97: library part C0017-A.9, "CAP CHIP 0402 1uF 10V X5R 10%", Case Code (Imperial)=0402, Case Code (Metric)=1005, Dielectric=X5R, Manufacturer=KEMET, Manufacturer 2=AVX, Manufacturer Part Number 2=GRM155R61A105KE15D, Tolerance=10%, Voltage=10V
C12 C83 C116 C118 C119 C120 C121 C122 C123 C124 C129: library part C0111-A.2, "CAP CHIP 0805 22uF 25V X5R 20%", Case Code (Imperial)=0805, Manufacturer="Samsung Electro-Mechanics", Tolerance=20%, Voltage=25V
C22 C23: library part C0033-A.9, "CAP CHIP 0402 22NF 10V X7R 10%", Case Code (Imperial)=0402, Case Code (Metric)=1005, Dielectric=X7R, Manufacturer="Samsung Electro-Mechanics", Tolerance=10%, Voltage=10V
C39 C40 C44 C45: library part C0073-A.7, "CAP CHIP 0402 1.8NF 25V C0G 5%", Case Code (Imperial)=0402, Case Code (Metric)=1005, Dielectric=C0G, Manufacturer=KEMET, Tolerance=5%, Voltage=25V
C46 C50 C128 C147: library part C0074-A.7, "CAP CHIP 0402 150PF 50V C0G 1%", Case Code (Imperial)=0402, Case Code (Metric)=1005, Dielectric=C0G, Manufacturer=Murata, Tolerance=1%, Voltage=50V
C57: library part C0044-A.4, "CAP CHIP 0603 1uF 25V X5R 10%", Case Code (Imperial)=0603, Case Code (Metric)=1608, Dielectric=X5R, Manufacturer=KEMET, Manufacturer 2=AVX, Manufacturer Part Number 2=06033D105KAT4A, Tolerance=10%, Voltage=25V
C64: library part C0116-A.1, "CAP CHIP 1206 68UF 10V X5R 20%", Case Code (Imperial)=1206, Case Code (Metric)=3216, Case/Package=0805, Dielectric=X5R, Manufacturer=TDK, Tolerance=20%, Voltage=10V
C65 C66 C68 C70 C71 C72 C73 C74 C75: library part C0007-A.9, "CAP CHIP 0402 1nF 50V X7R 10%", Case Code (Imperial)=0402, Case Code (Metric)=1005, Dielectric=X7R, Manufacturer=KEMET, Manufacturer 2=Murata, Manufacturer Part Number 2=GRM155R71H102KA01D, Tolerance=10%, Voltage=50V
C80 C157 C158: library part C0059-A.9, "CAP CHIP 0805 4.7nF 1000V X7R 10%", Case Code (Imperial)=0805, Case Code (Metric)=2012, Dielectric=X7R, Manufacturer=KEMET, Tolerance=10%, Voltage=1kV
C84: library part C0036-A.9, "CAP CHIP 0402 47nF 50V X5R 10%", Case Code (Imperial)=0402, Case Code (Metric)=1005, Dielectric=X5R, Manufacturer=Murata, Tolerance=10%, Voltage=50V
C85 C104 C106 C125 C126 C130 C131 C132 C133 C140: library part C0098-A.5, "CAP CHIP 0603 47UF X5R 20%", Case Code (Imperial)=0603, Case Code (Metric)=1608, Dielectric=X5R, Manufacturer=Murata, Max Operating Temperature=85°C, Min Operating Temperature=-55°C, Tolerance=20%, Voltage=6.3V
C86: library part C0037-A.9, "CAP CHIP 0402 4.7uF 6V3 X5R 20%", Case Code (Imperial)=0402, Case Code (Metric)=1005, Dielectric=X5R, Manufacturer=Murata, Tolerance=20%, Voltage=6.3V
C107 C112: library part C0026-A.11, "CAP CHIP 0402 18pF C0G 50V 5%", Case Code (Imperial)=0402, Case Code (Metric)=1005, Dielectric=C0G, Manufacturer=KEMET, Manufacturer 2=AVX, Manufacturer Part Number 2=04025A180JAT2A, Tolerance=5%, Voltage=50V
C108 C111 C117: library part C0031-A.9, "CAP CHIP 0402 2.2uF 6.3V X5R 10%", Case Code (Imperial)=0402, Case Code (Metric)=1005, Dielectric=X5R, Manufacturer=Murata, Tolerance=10%, Voltage=6.3V
C153 C154 C155 C156: library part C0097-A.6, "CAP CHIP 0402 47PF 25V C0G 5%", Case Code (Imperial)=0402, Case Code (Metric)=1005, Dielectric=C0G, Manufacturer=Yageo, Max Operating Temperature=125°C, Min Operating Temperature=-55°C, Tolerance=5%, Voltage=25V
CN1: library part J0089-A.6, "CONN HEADER SMD 10POS 2x5 1.27MM JTAG", Color=Black, Current Rating=1.75A, Manufacturer=Samtec, Max Operating Temperature=125°C, Min Operating Temperature=-55°C, Package Quantity=1
CN2 CN3: library part J0068-A.5, "CONN CONN STRIP THD 1,27 M/2/D 10v AuF H6,3 JTAG", Manufacturer="Adam Tech"
D1 D2 D3 D4 D9 D12: library part D0027-A.3, "DIODE TVS SMD 0402 14V 40V", Manufacturer="Littelfuse Inc"
D5 D6 D7 D8: library part D0025-A.3, "TVS ARRAY 4LIN.8kV 1pF SOT143B", Manufacturer=Nexperia
D10: library part D0031-A.3, "DIODE TVS 5V 19V SOD323", Manufacturer=Nexperia
D11: library part D0050-A.2, "DIODE ARRAY GP 100V 150MA SOT883", Forward Current=150mA, Manufacturer=Nexperia, Max Reverse Voltage (DC)=100V
D13 D14 D15 D16: library part D0027-A.4, "DIODE TVS SMD 0402 14V 40V", Manufacturer="Littelfuse Inc"
F1: library part P0009-2, "PTC SMD 30V 500MA 1812", Case Code (Imperial)=1812, Case Code (Metric)=4532, Hold Current=500mA, Manufacturer=Bel, Max Current Rating=100A, Max Operating Temperature=85°C, Min Operating Temperature=-40°C, Package Quantity=1, Trip Current=1A
Fiducial_1 Fiducial_2 Fiducial_3: library part UT0024-A.6
H1 H2 H3 H4: library part S0014-A.1, "RND STANDOFF 7MM M2.5X0.45 STEEL", Manufacturer="Wurth Elektronik"
J1: library part J0016-A.9, "CONN RCPT FEMALE D80POS 0.4MM SMD GOLD", Current Rating=300mA, Manufacturer=Hirose, Package Quantity=1, Part Number=DF40HC(3.5)-80DS-0.4V(51), Voltage Rating=30V
J2: library part J0153-A.2, "CONN RCPT FEMALE D80POS 0.4MM SMD GOLD", Current Rating=300mA, Manufacturer=Hirose, Package Quantity=1, Part Number=DF40HC(3.5)-80DS-0.4V(51), Voltage Rating=30V
J3 J9: library part J0084-A.2, "CONN PCB JACK RECEPTACLE SMA RA 50 OHM", Case/Package=SMA, Dielectric Material=PTFE, Frequency=12Hz, Housing Color=Gold, Manufacturer=Molex, Max Frequency=18GHz, Max Operating Temperature=165°C, Min Operating Temperature=-65°C, Package Quantity=1760, Voltage Rating=500V
J4: library part J0081-A.3, "CONN FPC VERT 20POS 1.00MM SMD", Contact Current Rating=1A, Flammability Rating="UL94 V-0", Housing Color=Black, Manufacturer="TE Connectivity", Max Operating Temperature=185°C, Min Operating Temperature=-4°C, Package Quantity=1000, Voltage Rating=125V
J5: library part J0031-A.3, "CONN BOARD STACKER HDR 40 POS 1.27mm ST SMD", Manufacturer=Samtec
J6: library part J0086-A.3, "CONN MOD JACK 6P6C R/A UNSHLD", Color=Black, Current Rating=1.5A, Flammability Rating="UL94 V-0", Insulation Resistance=500MR, Manufacturer="Wurth Electronics", Max Operating Temperature=85°C, Min Operating Temperature=-40°C, Package Quantity=120, Voltage Rating (AC)=120V
J7: library part J0085-A.3, "CONN MOD JACK 4P4C R/A UNSHLD", Manufacturer="Wurth Electronics", Max Operating Temperature=85°C, Min Operating Temperature=-40°C, Package Quantity=140
J8: library part J0186-A.4, "CONN PCI EXP MINI FEMALE 52POS Center board heigth 7.95mm", Flammability Rating="UL94 V-0", High Temperature Housing=Yes, Housing Color=Black, Manufacturer="TE Connectivity", Package Quantity=500
J10 J19: library part J0039-A.3, "CONN USB MICRO F/90^ SMD TipoAB 5x1", Manufacturer=Hirose
J11: library part J0011-A.4, "CONN Micro SD", Manufacturer=Amphenol
J12 J13 J14: library part J0020-A.3, "CONN JACK STEREO 3.5MM SMD R/A", Case/Package=SMD/SMT, Color=Black, Current Rating=1A, Manufacturer=CUI
J15: library part J0087-A.2, "CONN RCPT USB2.0 TYPEA STACK R/A", Color=White, Current Rating=1A, Flammability Rating="UL94 V-0", Insulation Resistance=1GR, Manufacturer="Wurth Electronics", Max Operating Temperature=105°C, Min Operating Temperature=-40°C, Package Quantity=100, Voltage Rating=30V
J16 J18: library part J0053-A.5, "CONN BATTERY HOLDER 18650 CLIP SMT", Manufacturer="Keystone Electronics"
J17: library part J0027-A.4, "CONN ETHERNET 1GIGABIT", Manufacturer=TRXCOM
J20: library part J0003-A.4, "CONN GROVE EQUIV THD 90 4POS", Manufacturer=Seeed, Manufacturer 2=4UCON, Manufacturer Part Number 2=20TW-870
L1: library part I0023-A.4, "IND CHIP 0402 39NH", Current=250mA, Manufacturer=Murata
L2: library part I0020-A.4, "IND CHIP 0402 68NH 250MA 5%", Current=250mA, Manufacturer=Murata
L3 L5: library part I0017-A.6, "IND FIXED 2.2UH 4A 61 MOHM SMD", Current=4A, Manufacturer=Bourns
L4: library part I0021-A.3, "FERRITE SMD 0603 220 OHM 2A", Case Code (Imperial)=0603, Case Code (Metric)=1608, Current=2A, DC Resistance (DCR)=50mR, Frequency=100MHz, Manufacturer=Murata, Max Operating Temperature=125°C, Min Operating Temperature=-55°C, Package Quantity=1, Tolerance=25%
L6: library part I0049-A.3, "IND FIXED SMD 3.3UH 3.5A 76 mOHM", Current=4A, DC Resistance (DCR)=76mR, Manufacturer=Bourns, Max Operating Temperature=150°C, Min Operating Temperature=-40°C, Test Frequency=100kHz, Tolerance=20%
PB1 PB2: library part B0006-A.6, "PUSHBUTTON SMD PTS820 NO HOLES", Color=Black, Manufacturer=C&K, Max Operating Temperature=85°C, Min Operating Temperature=-40°C
Q1 Q5 Q6 Q7: library part T0023-A.5, "MOSFET 2N-CH 50V 0.28A SOT-563", Case/Package=SOT-563, Continuous Drain Current (ID)=280mA, Drain to Source Breakdown Voltage=50V, Drain to Source Resistance=2R, Gate to Source Voltage (Vgs)=20V, Input Capacitance=50pF, Manufacturer="Diodes Incorporated", Max Operating Temperature=150°C, Max Power Dissipation=250mW, Min Operating Temperature=-55°C, Package Quantity=3000
Q4: library part T0010-A.6, "MOSFET P-CH 30V 4,5A 65mR SC70-6", Manufacturer=Vishay
R1 R2 R14 R18 R43 R45 R46 R47 R48 R49 R52 R59 R78 R84 R85 R118: library part R0058-A.5, "RES CHIP 0402 1M 1% 1/16W", Case Code (Imperial)=0402, Case Code (Metric)=1005, Manufacturer=Vishay, Manufacturer 2=Panasonic, Manufacturer Part Number 2=ERJ-2RKF1004X, Power=63mW, Tolerance=1%
R3 R17 R24 R25 R28 R29 R41 R42 R57 R77 R87 R111 R112: library part R0001-A.5, "RES CHIP 0402 100K 1% 1/16W", Case Code (Imperial)=0402, Case Code (Metric)=1005, Manufacturer=Vishay, Manufacturer 2=Panasonic, Manufacturer Part Number 2=ERJ-2RKF1003X, Power=63mW, Tolerance=1%
R4 R5 R6 R7 R8 R9 R12 R13 R15 R16 R19 R20 R21 R30 R31 R40 R44 R51 R60 R61 R62 R63 R69 R80 R83 R86 R90 R91 R93 R94 R99 R102 R103 R104 R105 R106 R107 R108 R109 R110 R113 R114 R115 R119: library part R0000-A.5, "RES CHIP 0402 0R 1/16W", Case Code (Imperial)=0402, Case Code (Metric)=1005, Manufacturer=Vishay, Manufacturer 2=Panasonic, Manufacturer Part Number 2=ERJ-S020R00X, Power=63mW, Tolerance=J
R10 R11 R53 R54 R56 R68 R70 R71 R74 R75 R76 R81 R89 R116 R117 R122: library part R0003-A.5, "RES CHIP 0402 10K 1% 1/16W", Case Code (Imperial)=0402, Case Code (Metric)=1005, Manufacturer=Vishay, Manufacturer 2=Panasonic, Manufacturer Part Number 2=ERJ-2RKF1002X, Power=63mW, Tolerance=1%
R22: library part R0076-A.6, "RES CHIP 0402 47K5 1% 1/16W", Case Code (Imperial)=0402, Case Code (Metric)=1005, Manufacturer=Vishay, Manufacturer 2=Panasonic, Manufacturer Part Number 2=ERJ-2RKF4752X, Power=63mW, Tolerance=1%
R23: library part R0144-A.3, "RES CHIP 0402 22R1 1% 1/16W", Case Code (Imperial)=0402, Case Code (Metric)=1005, Manufacturer=Vishay, Manufacturer 2=Panasonic, Manufacturer Part Number 2=ERJ-2RKF2212X, Power=63mW, Tolerance=1%
R26 R27: library part R0143-A.3, "RES CHIP 0402 51R1 1% 1/16W", Case Code (Imperial)=0402, Case Code (Metric)=1005, Manufacturer=Yageo, Manufacturer 2=Panasonic, Manufacturer Part Number 2=ERJ-2RKF51R1X, Power=63mW, Tolerance=1%
R32 R33 R37 R38: library part R0042-A.6, "RES CHIP 0402 100R 5% 1/16W", Case Code (Imperial)=0402, Case Code (Metric)=1005, Manufacturer=Vishay, Manufacturer 2=Panasonic, Manufacturer Part Number 2=ERJ-2GEJ101X, Power=63mW, Tolerance=5%
R34 R35: library part R0166-A.4, "RES CHIP 0402 2K 5% 1/16W", Case Code (Imperial)=0402, Case Code (Metric)=1005, Manufacturer=Vishay, Manufacturer 2=Panasonic, Manufacturer Part Number 2=ERJ-2GEJ202X, Power=63mW, Tolerance=1%
R36 R39: library part R0139-A.3, "RES CHIP 0402 3k 5% 1/16W", Case Code (Imperial)=0402, Case Code (Metric)=1005, Manufacturer=Vishay, Manufacturer 2=Panasonic, Manufacturer Part Number 2=ERJ-2GEJ302X, Power=63mW, Tolerance=1%
R50 R120 R123: library part R0043-A.4, "RES CHIP 0402 14K3 1/16W 1%", Case Code (Imperial)=0402, Case Code (Metric)=1005, Manufacturer=Vishay, Manufacturer 2=Panasonic, Manufacturer Part Number 2=ERJ-2RKF1432X, Power=63mW, Tolerance=1%
R55: library part R0167-A.4, "RES CHIP 0402 12K 0.5% 1/16W", Case Code (Imperial)=0402, Case Code (Metric)=1005, Manufacturer=Susumu, Power=63mW, Tolerance=0.5%
R58: library part R0050-A.5, "RES CHIP 0402 53.6K 1% 1/16W", Case Code (Imperial)=0402, Case Code (Metric)=1005, Manufacturer=Vishay, Manufacturer 2=Panasonic, Manufacturer Part Number 2=ERJ-2RKF5362X, Power=63mW, Tolerance=1%
R64: library part R0046-A.7, "RES CHIP 0402 49R9 1% 1/16W", Case Code (Imperial)=0402, Case Code (Metric)=1005, Manufacturer=Vishay, Manufacturer 2=Panasonic, Manufacturer Part Number 2=ERJ-2RKF49R9X, Max Operating Temperature=155°C, Max Power Dissipation=100mW, Min Operating Temperature=-55°C, Package Quantity=1, Power=63mW, Resistance=49.9R, Temperature Coefficient=100ppm/°C, Tolerance=1%, Voltage Rating=50V
R65 R88: library part R0172-A.6, "RES CHIP 0402 34K OHM 1% 1/16W", Case Code (Imperial)=0402, Case Code (Metric)=1005, Manufacturer=Yageo, Max Operating Temperature=155°C, Max Power Dissipation=63mW, Min Operating Temperature=-55°C, Package Quantity=10000, Power Rating=62.5mW, Resistance=34kR, Temperature Coefficient=100ppm/°C, Tolerance=1%, Voltage Rating=50V
R66: library part R0037-A.6, "RES CHIP 0402 75K 1% 1/16W", Case Code (Imperial)=0402, Case Code (Metric)=1005, Manufacturer=Yageo, Manufacturer 2=Panasonic, Manufacturer Part Number 2=ERJ-2RKF7502X, Power=63mW, Tolerance=5%
R67: library part R0020-A.5, "RES CHIP 0402 3K3 1% 1/16W", Case Code (Imperial)=0402, Case Code (Metric)=1005, Manufacturer=Yageo, Power=63mW, Tolerance=1%
R72: library part R0031-A.6, "RES CHIP 0402 100R 1% 1/16W", Case Code (Imperial)=0402, Case Code (Metric)=1005, Manufacturer=Vishay, Manufacturer 2=Panasonic, Manufacturer Part Number 2=ERJ-2RKF1000X, Power=63mW, Tolerance=1%
R73 R121 R124: library part R0014-A.5, "RES CHIP 0402 5K49 1% 1/16W", Case Code (Imperial)=0402, Case Code (Metric)=1005, Manufacturer=Vishay, Manufacturer 2=Panasonic, Manufacturer Part Number 2=ERJ-2RKF5491X, Power=63mW, Tolerance=1%
R79 R82: library part R0007-A.5, "RES CHIP 0402 1K 1% 1/16W", Case Code (Imperial)=0402, Case Code (Metric)=1005, Manufacturer=Vishay, Manufacturer 2=Panasonic, Manufacturer Part Number 2=ERJ-2RKF1001X, Power=63mW, Tolerance=1%
R92: library part R0131-A.3, "RES CHIP 0805 0R 1/8W", Case Code (Imperial)=0805, Case Code (Metric)=2012, Manufacturer=Vishay, Power=125mW, Tolerance=J
R95 R96: library part R0055-A.6, "RES CHIP 0402 470R 5% 1/16W", Case Code (Imperial)=0402, Case Code (Metric)=1005, Manufacturer=Vishay, Manufacturer 2=Panasonic, Manufacturer Part Number 2=ERJ-2GEJ471X, Power=63mW, Tolerance=1%
R97 R98 R100 R101: library part R0009-A.5, "RES CHIP 0402 22R 1% 1/16W", Case Code (Imperial)=0402, Case Code (Metric)=1005, Manufacturer=Yageo, Power=63mW, Tolerance=1%
SIM1 SIM2: library part J0149-A.2, "CONN SIM NANO HINGED, 6P, 1.40MM PROF", Manufacturer=GCT
SW1: library part S0022-A.1, "Switch DIP normally open", Contact Resistance=100mR, Current Rating=25mA, Manufacturer="CTS Corporation", Max Operating Temperature=85°C, Max Voltage Rating (DC)=24V, Min Operating Temperature=-55°C, Package Quantity=145
SW2: library part S0016-A.2, "DIP SWITCH SPST LATCHED SMD 0.025A, 24VDC, NORMALLY ON", Contact Resistance=100mR, Current Rating=25mA, Manufacturer="CTS Corporation", Max Operating Temperature=85°C, Max Voltage Rating (DC)=24V, Min Operating Temperature=-55°C, Package Quantity=145, Part Number=218-2LPSTR
U1: library part M0006-A.4, "MODULE RF TXRX CELL 4G LTE CATM1/NB-IOT", Manufacturer=UBlox
U2: library part U0053-A.4, "IC CODEC STER HDPN & SPKR 40QFN", Case/Package=QFN, Manufacturer="Cirrus Logic", Max Operating Temperature=85°C, Min Operating Temperature=-40°C, Operating Supply Voltage=2.5V, Package Quantity=50
U3: library part U0115-A.4, "IC USB 2.0 4PORT HUB CTLR 36QFN", Case/Package=QFN, Manufacturer=Microchip, Max Operating Temperature=85°C, Max Supply Voltage=3.6V, Min Operating Temperature=-40°C, Min Supply Voltage=3V, Operating Supply Current=70mA, Operating Supply Voltage=3.3V
U4: library part U0145-A.2, "Line Transceiver, 2 Func, 2 Driver, 2 Rcvr", Manufacturer=MaxLinear
U5: library part U0114-A.4, "IC CAN TRANSCEIVER 1Mbps STBY 5.25V SOIC8", Case/Package=SOIC, Manufacturer=NXP, Max Operating Temperature=150°C, Max Supply Voltage=5.25V, Min Operating Temperature=-40°C, Min Supply Voltage=4.75V
U6: library part U0050-A.6, "IC DC/DC POWER MODULE 36V 5A LGA18", Manufacturer=MPS, Part Number=MPM3550E
U7: library part U0052-A.5, "IC POWER SWITCH DUAL CHANNEL OCP", Manufacturer="ON Semiconductor", Max Input Voltage=5.5V, Max Operating Temperature=85°C, Max Output Current=2.5A, Max Power Dissipation=850mW, Max Supply Current=1uA, Min Input Voltage=2.7V, Min Operating Temperature=-40°C, On-State Resistance=95mR, Package Quantity=3000
U8 U20 U21 U22: library part U0019-A.7, "IC TRANSLATOR BIDIR 1CH", Case/Package=SC70, Manufacturer="Texas Instruments"
U9: library part X0013-A.3, "MEMS OSC 12MHz VDD 1.7V to 3.6V VFLGA 1.6mm x 1.2mm", Manufacturer=Microchip
U10: library part U0083-A.6, "IC BUS.BUFFER GATE   SC70-5 (SOT353)", Manufacturer="Texas Instruments"
U11: library part U0194-A.2, "IC BATTERY CHARGER 4.5A VQFN24", Case/Package=VQFN24, Manufacturer="Texas Instruments", Max Operating Temperature=85°C, Min Operating Temperature=-40°C
U12: library part U0110-A.3, "IC V-REG LDO 1.8V 150mA  SOT25", Case/Package=SOT-25, Manufacturer="Diodes Inc", Max Input Voltage=6V, Max Operating Temperature=85°C, Max Output Current=150mA, Max Power Dissipation=640mW, Min Current Limit=200mA, Min Input Voltage=2V, Min Operating Temperature=-40°C, Output Voltage=1.8V, Package Quantity=3000, Power Dissipation=640W, Quiescent Current=55uA
U13: library part U0092-A.5, "IC REG BUCK ADJ 6A SYNC 14VQFN", Case/Package=VQFN, Manufacturer="Texas Instruments", Max Input Voltage=17V, Max Operating Temperature=150°C, Max Output Current=6A, Max Output Voltage=15V, Min Input Voltage=4.5V, Min Operating Temperature=-40°C, Min Output Voltage=800mV, Package Quantity=3000, Quiescent Current=600uA, Switching Frequency=1.6MHz
U14: library part U0027-A.6, "IC V-REG LDO 3V3 600mA +En  SOT25", Manufacturer="Diodes Inc"
U15: library part U0118-A.4, "MCU 32-bit STM32F ARM Cortex M4F RISC 1024KB Flash 2.5V/3.3V 64-Pin LQFP Tray", Case/Package=LQFP, Frequency=168MHz, Manufacturer="ST Microelectronics", Max Operating Temperature=85°C, Max Supply Voltage=3.6V, Min Operating Temperature=-40°C, Min Supply Voltage=1.8V, Package Quantity=960
U16 U17 U18 U19: library part U0119-A.4, "IC SINGLE 2-INPUT MUX 6TSSOP", Case/Package=TSSOP, Manufacturer=Nexperia, Max Operating Temperature=125°C, Max Supply Voltage=5.5V, Min Operating Temperature=-40°C, Min Supply Voltage=1.65V
U23: library part M0000-A.4, "MODULE LoRa", Manufacturer=Murata
U24 U25: library part U0192-A.2, "IC IDEAL DIODE 2.3V-23V 5.5A QFN 2mm", Manufacturer="Texas Instruments", Max Supply Voltage=28V
X1: library part J0083-A.5, "CONN PWR JACK 2X5.5MM SOLDER", Color=Black, Current Rating=2.5A, Flammability Rating="UL94 V-0", Insulation Resistance=50MR, Manufacturer=CUI, Max Operating Temperature=85°C, Min Operating Temperature=-25°C, Package Quantity=280, Voltage Rating=24V
Y1: library part X0005-A.4, "CRYSTAL 24.0000MHZ 18PF SMD", ESR (Equivalent Series Resistance)=60, Frequency=24MHz, Frequency Stability=30ppm, Frequency Tolerance=20ppm, Load Capacitance=18pF, Manufacturer=Kyocera, Max Operating Temperature=85°C, Min Operating Temperature=-40°C, Series Resistance=60R
Y3: library part X0003-A.4, "CRYSTAL 32.768kHz 20ppm 12.5pF SMD 1.6x0.9mm", Frequency=32.768kHz, Frequency Stability=0.12%, Frequency Tolerance=20ppm, Load Capacitance=12.5pF, Manufacturer="Citizen FineDevice", Max Operating Temperature=85°C, Min Operating Temperature=-40°C, Series Resistance=70kR

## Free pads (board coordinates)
  round 3.2 hole 3.2 unplated: 13(3.3,7.2) 13(3.3,97.6)
  round 2.25 hole 2.25 unplated: 13(65.278,2.032) 14(43.942,2.032) 15(43.942,64.008) 16(65.278,64.008)
  round 2.25 hole 3.2 unplated: 13(98.3,7.2) 13(98.3,97.6)

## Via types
v1: diameter 0.4, hole 0.2, Top Layer to Bottom Layer, tented both sides, 1471 vias

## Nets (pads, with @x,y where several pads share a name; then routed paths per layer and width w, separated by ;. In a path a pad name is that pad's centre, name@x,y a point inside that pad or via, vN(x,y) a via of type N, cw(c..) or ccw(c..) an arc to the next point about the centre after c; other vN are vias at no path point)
485/232n_1: 485/232n.X J2.61 R78.2 U4.14 | length 71.6
  Top Layer w0.15: J2.61@58.81,61.865 58.81,62.339 59.511,63.04 63.153,63.04 64.214,61.979 65.357,61.979 67.478,59.858 67.478,59.645 68.195,58.928 69.392,58.928 v1(70.443,57.877)
  Top Layer w0.2: R78.2@73.9,20.5 v1(74.436,20.5) 74.73,20.5 75.28,19.95 76.123,19.95 76.55,19.523 U4.14@76.55,19.025
  Bottom Layer w0.2: v1(70.443,57.877) 70.519,57.877 73.295,55.101 75.685,55.101 80.04,50.745 80.04,36.078 81.132,34.986 81.132,27.593 78.039,24.5 75.9,24.5 74.875,23.475 74.394,22.993 74.394,20.5 74.436,20.458 74.436,19.179 74.644,18.971 74.644,17.919 74.25,17.525 74.25,15.75 485/232n.X@75,15
+1V8: 1V8.X C24.2 C25.2 C26.2 C27.2 C28.2 C87.2 R22.2 U2.13 U2.16 U2.34 U12.5 | length 56
  Top Layer w0.2: C25.2@21.185,69.25 C28.2@21.185,70.25 U2.34@23.35,70.25 ; U2.13@29.15,68.25 30.06,68.25 v1(30.75,67.56) 30.86,67.45 C24.2@31.565,67.45 C27.2@31.565,68.45 C26.2@31.565,69.45 31.265,69.75 U2.16@29.15,69.75 ; v1(32.143,85.706) 32.154,85.706 32.36,85.5 R22.2@33.525,85.5
  Top Layer w0.25: U12.5@30.089,61.837 30.089,63.149 C87.2@30.1,63.16 30.893,63.16 v1(32.709,64.976)
  POWER w0.5: v1(21.872,70.246) 22.654,70.246 23.35,69.55 23.35,68.251 24.076,67.525 27.641,67.525 27.677,67.56 v1(30.75,67.56) 33.385,67.56 33.77,67.175 33.77,65.966 32.78,64.976 v1(32.709,64.976)
  Bottom Layer w0.2: v1(30.75,67.56) 30.126,68.184 30.126,69.526 31.985,71.385 31.985,80.89 31.25,81.625 31.25,85.103 31.367,85.22 31.657,85.22 v1(32.143,85.706)
  Bottom Layer w0.3: v1(32.709,64.976) 32.736,64.976 32.8,65.04 33.866,65.04 34.906,64 1V8.X@35,64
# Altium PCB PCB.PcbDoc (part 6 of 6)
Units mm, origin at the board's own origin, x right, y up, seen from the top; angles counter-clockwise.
Board outline 101.6 x 101.61 mm, 4 copper layers (Top Layer, GND, POWER, Bottom Layer), stack 1.371 mm thick; 504 components, 345 nets, 1794 pads, 1471 vias.

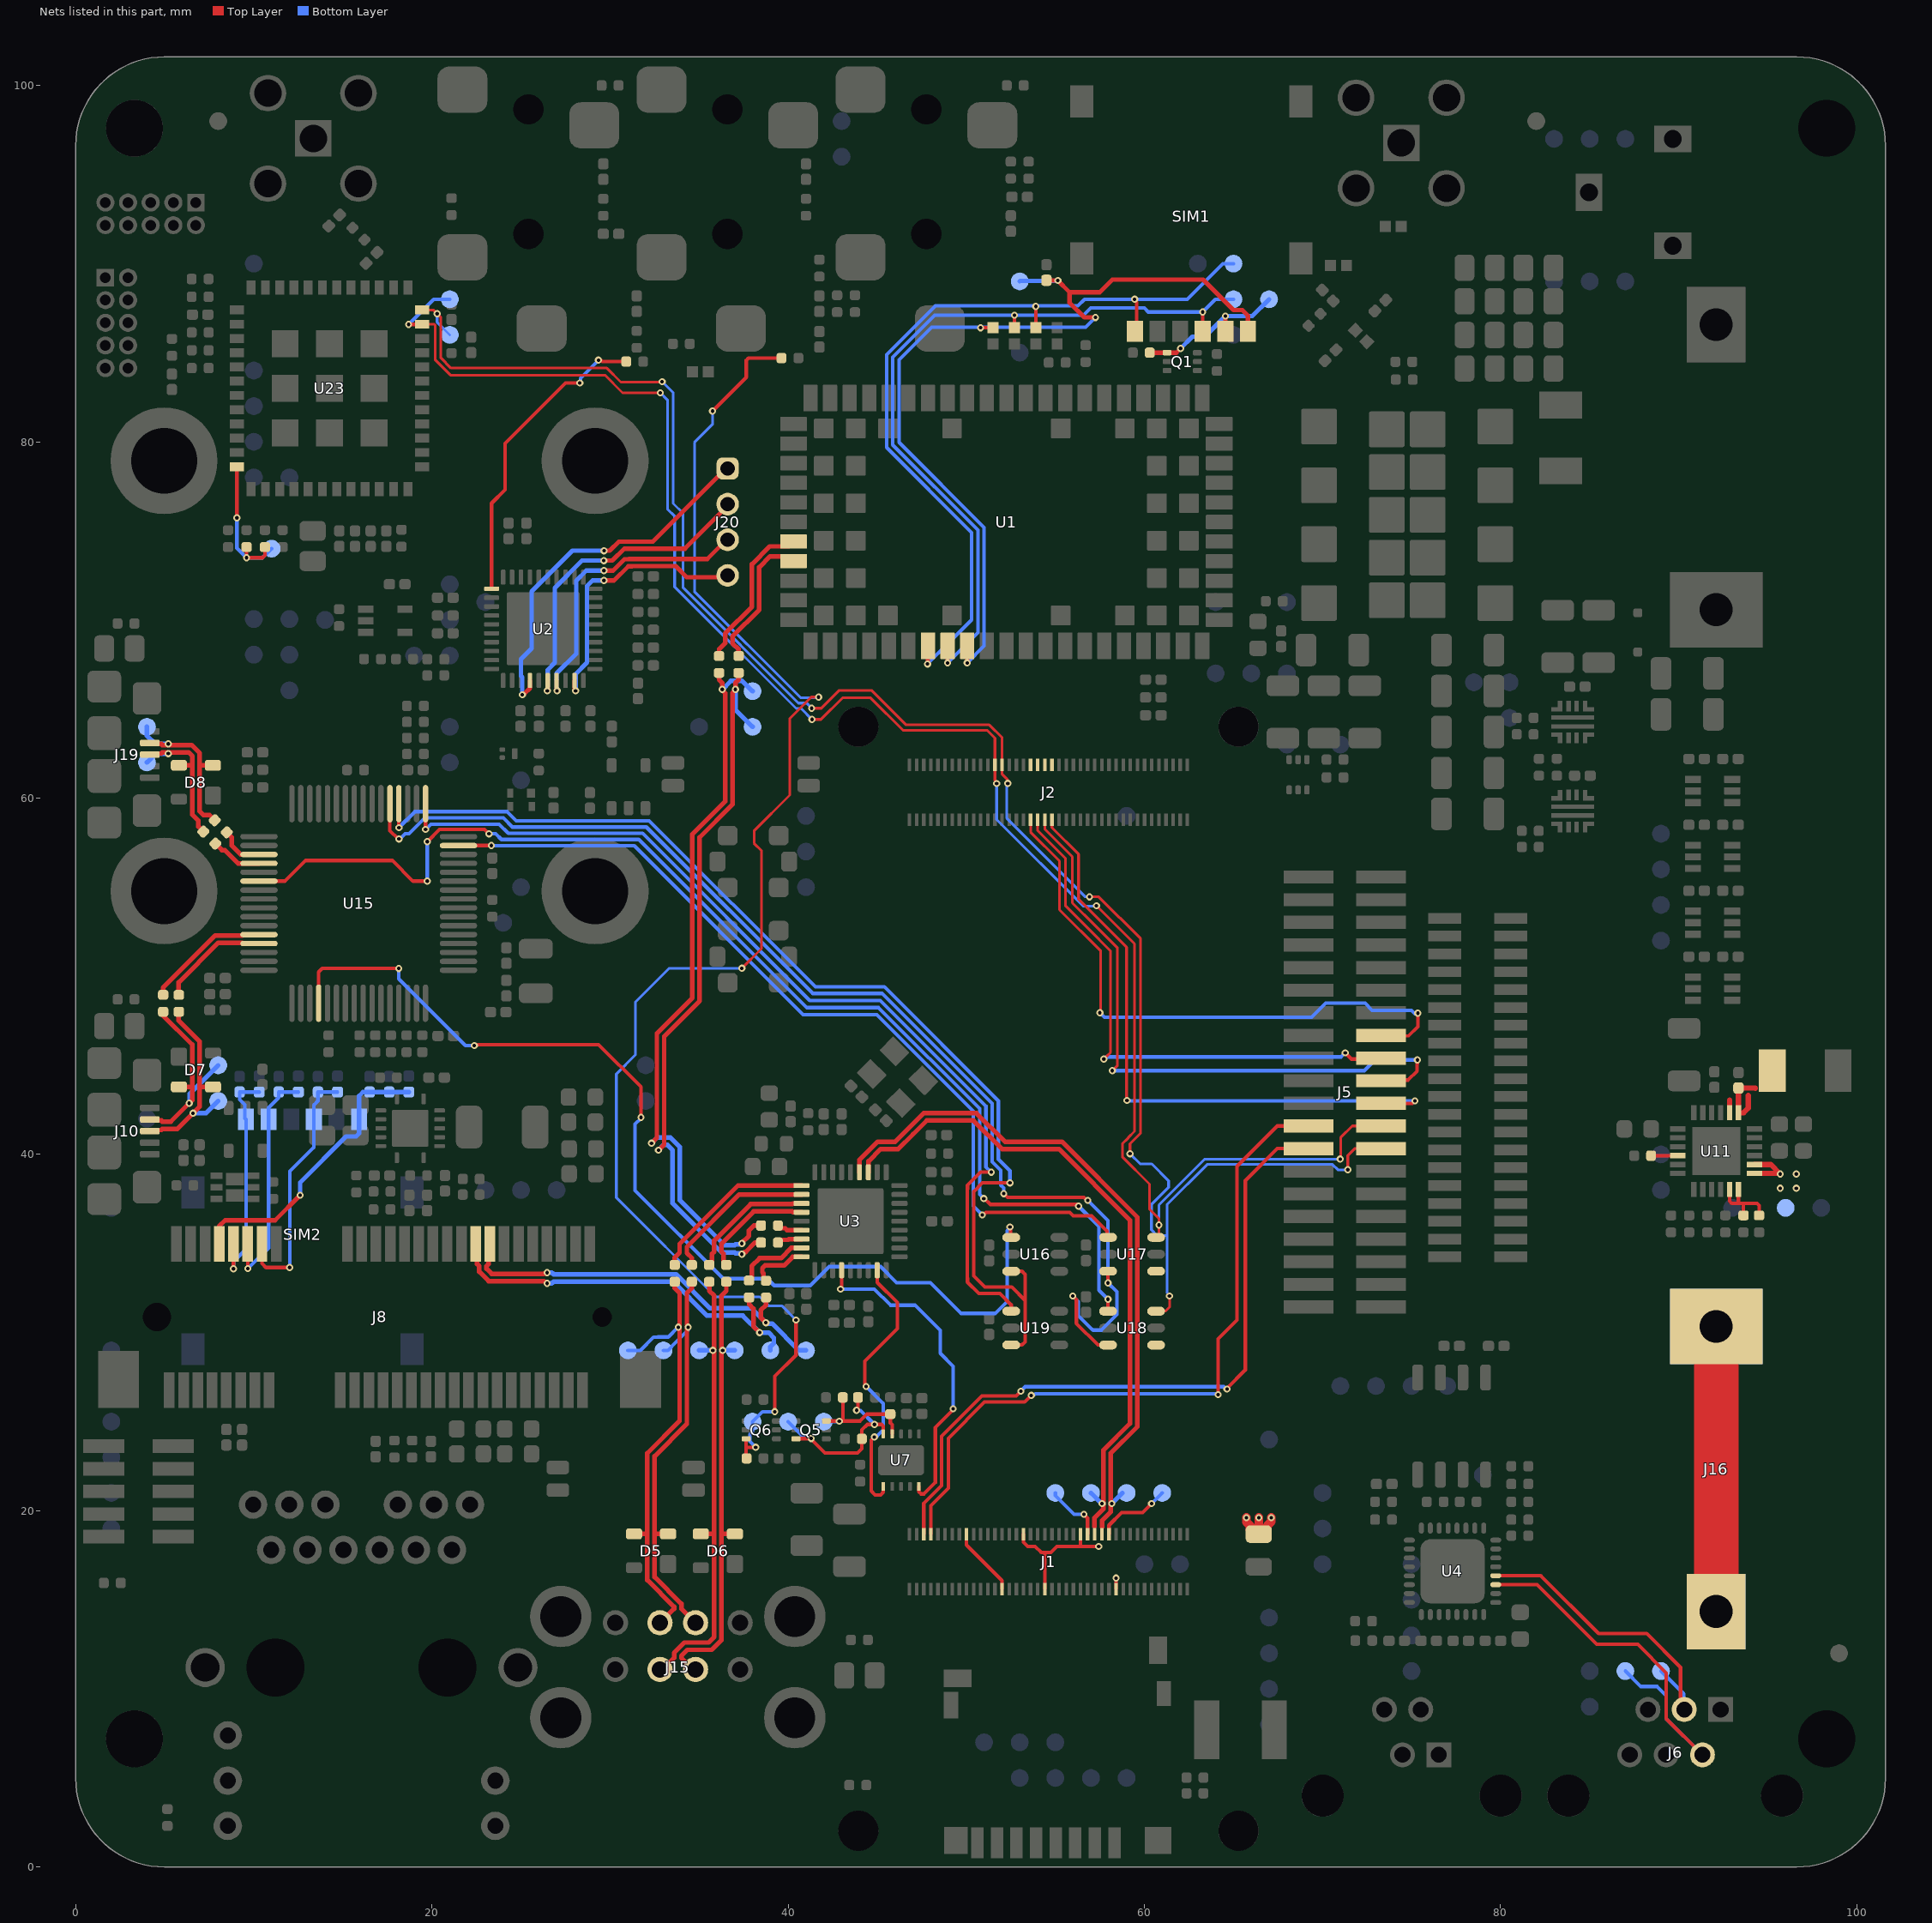
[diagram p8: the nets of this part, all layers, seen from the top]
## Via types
v1: diameter 0.4, hole 0.2, Top Layer to Bottom Layer, tented both sides, 1471 vias

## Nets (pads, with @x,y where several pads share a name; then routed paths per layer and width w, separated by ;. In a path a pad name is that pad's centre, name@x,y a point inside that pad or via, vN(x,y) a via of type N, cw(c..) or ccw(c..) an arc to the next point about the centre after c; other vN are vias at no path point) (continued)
SERIAL3.RX_1: J2.27 J5.26 SERIAL3_RX.X U18.3 U23.24 | length 107.2
  Top Layer w0.15: U23.24@19.45,87.4 20.077,87.4 v1(20.288,87.188) 20.501,86.975 20.501,84.704 21.067,84.138 29.817,84.138 30.605,83.35 32.9,83.35 v1(32.925,83.375) ; v1(41.317,65.044) 41.864,65.044 42.868,66.048 44.682,66.048 46.62,64.111 51.289,64.111 52.01,63.39 J2.27@52.01,61.865 52.01,61.341 52.308,61.043 52.308,60.846 v1(52.329,60.825) ; v1(56.913,54.456) 57.442,54.456 59.789,52.108 59.789,41.195 59.189,40.595 v1(59.189,40.038) ; U18.3@60.659,31.201 60.667,31.209 61.19,31.209 61.409,31.428 v1(61.409,32.051) ; v1(71.419,39.138) 71.419,39.938 71.806,40.325 J5.26@73.282,40.325
  Bottom Layer w0.15: v1(20.288,87.188) 20.288,86.712 SERIAL3_RX.X@21,86 ; v1(32.925,83.375) 33.541,82.759 33.541,76.539 34.1,75.98 34.1,71.803 40.574,65.329 41.033,65.329 v1(41.317,65.044) ; v1(52.329,60.825) 52.281,60.777 52.281,60.618 52.275,60.612 52.275,58.86 56.68,54.456 v1(56.913,54.456) ; v1(59.189,40.038) 59.762,39.465 60.413,39.465 61.359,38.52 61.359,38.148 60.394,37.183 60.394,35.773 60.719,35.447 61.275,35.447 ; v1(61.409,32.051) 61.409,32.086 61.275,32.22 61.275,35.447 ; v1(71.419,39.138) 70.859,39.138 70.559,39.438 63.519,39.438 61.275,37.194 61.275,35.447
SERIAL3.TX_1: J2.25 J5.24 SERIAL3_TX.X U17.3 U23.23 | length 102.5
  Top Layer w0.15: U23.23@19.45,86.6 20.13,86.6 20.174,86.556 20.174,84.607 21.043,83.738 29.715,83.738 30.703,82.75 v1(32.825,82.75) ; v1(41.335,64.418) 41.841,64.418 43.05,65.627 44.626,65.627 46.442,63.811 51.165,63.811 51.61,63.366 J2.25@51.61,61.865 51.61,60.987 51.708,60.889 v1(51.708,60.821) ; v1(57.309,53.958) 59.444,51.823 59.444,41.293 59.089,40.938 59.089,40.92 58.764,40.595 58.764,39.862 60.289,38.337 60.289,36.924 60.819,36.395 v1(60.819,36.038) 60.819,35.505 U17.3@60.659,35.345 ; v1(70.994,39.738) 71.019,39.763 71.019,40.938 71.676,41.595 J5.24@73.282,41.595
  Top Layer w0.2: v1@18.689,86.59 U23.23@19.44,86.59
  Bottom Layer w0.15: v1(32.825,82.75) 33.225,82.35 33.225,76.225 33.625,75.825 33.625,71.853 40.45,65.029 40.724,65.029 v1(41.335,64.418) ; v1(51.708,60.821) 51.708,58.794 56.564,53.938 57.289,53.938 v1(57.309,53.958) ; v1(60.819,36.038) 60.819,37.162 63.394,39.738 v1(70.994,39.738)
  Bottom Layer w0.2: v1(18.687,86.588) 20.1,88 SERIAL3_TX.X@21,88
SIO_5: D1.C SIM1.C7 SIM_IO.X U1.39 | length 46.1
  Top Layer w0.2: D1.C@53.9,86.4 v1(53.9,87.6) ; v1(59.45,88) 59.45,87.946 59.56,87.836 59.56,86.295 SIM1.C7@59.465,86.2
  Top Layer w0.25: v1(47.825,67.528) 47.837,67.54 47.837,68.538 U1.39@47.85,68.55
  Bottom Layer w0.2: v1(47.825,67.528) 49.009,68.711 50.3,70.002 50.3,74.9 45.522,79.678 45.522,84.885 48.265,87.628 56.267,87.628 56.639,88 v1(59.45,88) 62.407,88 64.4,89.993 64.993,89.993 SIM_IO.X@65,90
SPDIF.RX_1: J1.76 J5.25 | length 39.6
  Top Layer w0.2: J1.76@47.61,18.685 47.61,20.41 48.619,21.419 48.619,24.188 50.881,26.45 52.803,26.45 v1(53.061,26.708) ; v1(64.638,26.831) 64.638,26.876 65.665,27.903 65.665,38.535 67.455,40.325 J5.25@69.218,40.325
  Bottom Layer w0.2: v1(53.061,26.708) 53.314,26.961 64.454,26.961 64.584,26.831 v1(64.638,26.831)
SPDIF.TX_1: J1.74 J5.23 | length 40.2
  Top Layer w0.2: J1.74@48.01,18.685 48.01,20.284 48.992,21.266 48.992,24.066 51.026,26.1 53.272,26.1 v1(53.648,26.475) ; v1(64.134,26.511) 64.134,29.643 65.194,30.702 65.194,39.334 67.455,41.595 J5.23@69.218,41.595
  Bottom Layer w0.2: v1(53.648,26.475) 53.686,26.513 53.823,26.513 53.88,26.57 64.021,26.57 64.08,26.511 v1(64.134,26.511)
SPI0_CK: J2.37
SPI0_CS: J2.35
SPI0_MISO: J2.39
SPI0_MOSI: J2.41
SPI1.CK_1: J2.38 J5.18 | length 31.1
  Top Layer w0.15: J2.38@54.01,58.785 54.01,58.171 55.574,56.607 55.574,53.947 56.825,52.696 58.095,51.426 58.095,45.72 57.875,45.5 v1(57.725,45.35)
  Top Layer w0.2: v1(71.275,45.7) 71.625,45.35 73.227,45.35 J5.18@73.282,45.405
  Bottom Layer w0.2: v1(57.725,45.35) 57.85,45.475 71.05,45.475 v1(71.275,45.7)
SPI1.CS_1: J2.36 J5.16 | length 33.9
  Top Layer w0.15: J2.36@53.61,58.785 53.61,58.09 55.234,56.466 55.234,53.735 57.55,51.419 57.55,48 v1(57.5,47.95)
  Top Layer w0.19: J5.16@73.282,46.675 73.307,46.65 74.825,46.65 75.35,47.175 v1(75.35,47.925)
  Bottom Layer w0.19: v1(57.5,47.95) 57.76,47.69 69.39,47.69 70.19,48.49 72.39,48.49 72.79,48.09 74.99,48.09 v1@75.19,47.89
SPI1.MISO_1: J2.40 J5.20 | length 36.1
  Top Layer w0.15: J2.40@54.41,58.785 54.41,58.252 55.955,56.707 55.955,54.117 57.215,52.857 58.485,51.587 58.485,44.985 v1(58.2,44.7)
  Top Layer w0.2: J5.20@73.282,44.135 73.322,44.175 74.8,44.175 75.3,44.675 75.3,45.075 75.325,45.1 v1(75.325,45.3)
  Bottom Layer w0.2: v1(58.2,44.7) 72.35,44.7 72.95,45.3 v1(75.325,45.3)
SPI1.MOSI_1: J2.42 J5.22 | length 35.6
  Top Layer w0.15: J2.42@54.81,58.785 54.81,58.34 56.3,56.85 56.3,54.331 59,51.631 59,43.043 v1(59.019,43.024)
  Top Layer w0.2: J5.22@73.282,42.865 75.047,42.865 v1(75.182,43)
  Bottom Layer w0.2: v1(59.019,43.024) 59.043,43 v1(75.182,43)
SPK_OUTA+_4: J20.1 U2.4 | length 20.9
  Top Layer w0.25: v1(25.075,65.8) 25.115,65.8 25.176,65.861 25.195,65.861 25.5,66.166 U2.4@25.5,66.6 ; v1(29.659,73.882) 29.662,73.884 29.984,73.884 30.5,74.4 32.4,74.4 36.01,78.01 36.012,78.01 36.501,78.5 J20.1@36.6,78.5
  Bottom Layer w0.25: v1(25.075,65.8) 25.075,66.783 25,66.858 25,67.8 25.6,68.4 25.6,71.6 26.1,72.1 27.882,73.882 v1(29.659,73.882)
SPK_OUTA-_4: J20.2 U2.6 | length 18.2
  Top Layer w0.25: v1(26.475,66.025) 26.5,66.05 U2.6@26.5,66.6 ; v1(29.648,73.329) 30.129,73.329 30.8,74 34.2,74 36.6,76.4 J20.2@36.6,76.5
  Bottom Layer w0.25: v1(26.475,66.025) 26.503,66.053 26.503,67.203 26.9,67.6 26.9,71.8 28.429,73.329 v1(29.648,73.329)
SPK_OUTB+_4: J20.3 U2.7 | length 16.7
  Top Layer w0.25: U2.7@27,66.6 27,66.05 v1(27.025,66.025) ; v1(29.656,72.769) 30.169,72.769 30.814,73.414 31.058,73.414 ; 31.059,73.415 35.457,73.415 36.542,74.5 J20.3@36.6,74.5
  Bottom Layer w0.25: v1(27.025,66.025) 27,66.05 27,67 28.1,68.1 28.1,72.2 28.669,72.769 v1(29.656,72.769)
SPK_OUTB-_4: J20.4 U2.9 | length 15.4
  Top Layer w0.25: U2.9@28,66.6 28,66.129 28.063,66.066 v1(28.063,66.025) ; v1(29.656,72.213) 30.225,72.213 31.027,73.014 31.224,73.014 ; 31.224,73.015 33.685,73.015 34.3,72.4 36.5,72.4 J20.4@36.6,72.5
  Bottom Layer w0.25: v1(28.063,66.025) 28.063,66.963 28.7,67.6 28.7,71.9 29.013,72.213 v1(29.656,72.213)
SPKR/HP_4: R23.1 U2.31 | length 17.4
  Top Layer w0.2: U2.31@23.35,71.75 23.35,76.55 24.1,77.3 24.1,79.898 27.502,83.3 v1(28.3,83.3) ; v1(29.348,84.581) 29.386,84.543 29.528,84.543 29.558,84.513 R23.1@30.909,84.513
  Bottom Layer w0.2: v1(28.3,83.3) 28.337,83.337 28.337,83.57 v1(29.348,84.581)
SRST_5: D3.C SIM1.C2 SIM_SRST.X U1.40 | length 43.3
  Top Layer w0.2: D3.C@52.7,86.4 v1(52.7,87.1) ; v1(63.267,87.286) 63.267,86.208 SIM1.C2@63.275,86.2
  Top Layer w0.25: v1(48.95,67.589) U1.40@48.95,68.55
  Bottom Layer w0.2: v1(48.95,67.589) 50.65,69.288 50.65,75.045 45.872,79.823 45.872,84.74 48.233,87.1 52.616,87.1 52.7,87.184 52.784,87.1 56.583,87.1 56.993,87.51 59.991,87.51 60.215,87.286 v1(63.267,87.286) 63.981,88 SIM_SRST.X@65,88
SSW_5: Q1.1 R2.1 SIM1.C5 SIM_SSW.X | length 8.8
  Top Layer w0.25: R2.1@60.3,85 Q1.1@61.275,85 61.79,85 v1(62.028,85.239) ; SIM1.C5@64.545,86.2 v1(64.545,87.055)
  Bottom Layer w0.25: v1(62.028,85.239) 62.69,85.9 63.39,85.9 v1(64.545,87.055) 66.055,87.055 SIM_SSW.X@67,88
STAT_12: R71.1 U11.4 | length 1.5
  Top Layer w0.2: R71.1@88.445,39.93 U11.4@89.945,39.93
SVCC_5: C7.1 D9.C SIM1.C1 SIM_SVCC.X U1.41 | length 51.2
  Top Layer w0.2: v1(50.8,86.4) D9.C@51.5,86.4
  Top Layer w0.25: v1(50.05,67.589) U1.41@50.05,68.55 ; C7.1@54.5,89.065 54.507,89.058 55.134,89.058 v1(55.141,89.051) 55.8,88.392 ; v1(57.255,86.978) 56.622,86.978 55.8,87.8 55.8,88.392 ; SIM1.C1@65.815,86.2 65.815,87.085 65.5,87.4 65,87.4 63.3,89.1 58.2,89.1 57.492,88.392 55.8,88.392
  Bottom Layer w0.2: v1(50.05,67.589) 51,68.538 51,75.19 46.222,79.968 46.222,84.595 48.052,86.424 56.701,86.424 v1(57.255,86.978)
  Bottom Layer w0.25: SIM_SVCC.X@53,89 53.025,89.025 55.116,89.025 v1(55.141,89.051)
SW_bq_12: C84.2 L5.1 U11.19 U11.20 | length 4.7
  Top Layer w0.3: U11.20@92.85,42.335 92.85,43.05 ; U11.19@93.347,42.55 93.35,42.55 U11.19@93.35,42.335 ; 93.9,43.3 93.9,42.6 93.635,42.335 U11.19@93.35,42.335 ; 94.3,43.7 94.3,43.725 C84.2@93.35,43.725 U11.19@93.35,42.335
TS_bq_12: R73.1 R75.2 U11.11 U11.12 | length 4.4
  Top Layer w0.2: U11.11@92.85,38.025 92.85,37.373 92.967,37.256 93.403,37.256 ; U11.12@93.35,38.025 93.35,37.309 93.403,37.256 ; R75.2@93.632,36.575 93.632,37.256 ; R73.1@94.509,36.578 94.509,37.138 94.392,37.256 93.632,37.256 ; 93.403,37.256 93.632,37.256
U\S\B\_\E\N\0\_1: HUB_EN0.X Q5.6 R41.1 R114.2 U7.4 | length 7.1
  Top Layer w0.2: Q5.6@42.139,25.038 43.089,25.038 ; R114.2@43.069,26.358 43.069,25.058 43.089,25.038 ; U7.4@45.839,24.313 45.839,24.826 45.734,24.931 R41.1@45.734,25.423 44.424,25.423 44.039,25.038 43.089,25.038
  Bottom Layer w0.2: HUB_EN0.X@42,25 42.01,25.01 42.858,25.01 v1(42.868,25.02)
U\S\B\_\E\N\1\_1: HUB_EN1.X Q5.3 R42.1 R115.2 U7.5 | length 10.8
  Top Layer w0.2: Q5.3@40.439,24.038 40.447,24.046 41.289,24.046 v1(41.298,24.054) 41.298,24.003 42.063,23.238 43.889,23.238 44.139,23.488 R115.2@44.139,24.038 44.139,24.538 44.444,24.842 v1(44.844,24.842) 45.244,24.842 45.339,24.747 U7.5@45.339,24.313 ; v1(43.839,25.638) 43.839,25.692 43.919,25.772 R42.1@43.919,26.358
  Bottom Layer w0.2: HUB_EN1.X@40,25 40.946,24.054 v1(41.298,24.054) ; v1(43.839,25.638) 43.847,25.63 44.056,25.63 v1(44.844,24.842)
UART2_SNIFF_3: U15.17 U19.4 | length 53.8
  Top Layer w0.2: v1(19.639,58.238) U15.17@19.639,59.688 ; v1(51.4,39) 50.8,39 50.066,38.266 50.066,38.061 50.059,38.054 50.059,33.046 50.066,33.039 50.066,32.834 50.7,32.2 51.879,32.2 52.523,31.555 U19.4@52.523,31.205
  Bottom Layer w0.2: v1(19.639,58.238) 19.939,58.538 23.776,58.538 24.289,58.025 31.824,58.025 41.211,48.638 45.172,48.638 51.1,42.71 51.1,39.3 v1(51.4,39)
UART3_SNIFF_3: U15.52 U16.4 | length 58.8
  Top Layer w0.2: U15.52@13.639,48.488 13.639,50.238 13.839,50.438 v1(18.139,50.438) ; v1(22.381,46.11) 22.42,46.149 22.523,46.149 22.54,46.165 29.359,46.165 31.734,43.79 v1(31.734,42.074) ; v1(52.45,35.925) 52.487,35.889 52.487,35.378 U16.4@52.523,35.342
  Bottom Layer w0.2: v1(18.139,50.438) 18.139,49.851 21.88,46.11 v1(22.381,46.11) ; v1(31.734,42.074) 31.734,42.026 31.405,41.696 31.405,37.971 36.351,33.025 38.827,33.025 39.212,32.64 41.245,32.64 42.305,33.7 45.19,33.7 46.09,32.8 47.982,32.8 49.709,31.073 51.625,31.073 52.298,31.745 52.298,35.719 52.45,35.871 v1(52.45,35.925)
UART4_SNIFF_3: U15.15 U17.4 | length 49
  Top Layer w0.2: U15.15@21.489,57.338 v1(23.339,57.338) ; v1(50.9,36.6) 50.954,36.6 51.104,36.75 55.806,36.75 55.999,36.557 57.043,36.557 57.905,35.695 57.905,35.4 U17.4@57.959,35.345
  Bottom Layer w0.2: v1(23.339,57.338) 23.352,57.325 31.364,57.325 40.841,47.848 44.972,47.848 50.399,42.421 50.399,37.101 v1(50.9,36.6)
UART6_SNIFF_3: U15.38 U18.4 | length 67.6
  Top Layer w0.2: U15.38@10.289,55.338 11.743,55.338 12.906,56.5 17.778,56.5 18.94,55.338 v1(19.739,55.338) ; v1(19.739,57.553) 20.424,58.238 22.956,58.238 v1(23.2,57.994) ; v1(50.984,37.522) 51.028,37.522 51.357,37.193 56.207,37.193 v1(56.304,37.096) ; U18.4@57.959,31.201 v1(57.959,31.873)
  Bottom Layer w0.2: v1(19.739,55.338) v1(19.739,57.553) ; v1(23.2,57.994) 23.583,57.994 23.902,57.675 31.608,57.675 41.045,48.238 45.078,48.238 50.749,42.566 50.749,37.758 v1(50.984,37.522) ; v1(56.304,37.096) 57.454,35.946 57.454,32.378 v1(57.959,31.873)
UART_CH1-2_3: U15.20 U16.6 U19.6 | length 62.9
  Top Layer w0.2: U15.20@18.139,59.688 18.145,59.682 18.145,58.343 v1(18.15,58.338) ; v1(52.45,38.4) 50.9,38.4 50.409,37.909 50.409,33.191 51.05,32.55 52.55,32.55 53.301,31.799 ; U19.6@52.523,29.305 53.123,29.305 53.301,29.483 53.301,31.799 ; U16.6@52.523,33.442 53.123,33.442 53.301,33.264 53.301,31.799
  Bottom Layer w0.2: v1(18.15,58.338) 18.15,58.348 19.039,59.238 24.22,59.238 24.732,58.725 32.202,58.725 41.526,49.4 45.4,49.4 51.8,43 51.8,39.731 52.45,39.081 v1(52.45,38.4)
UART_CH3-4_3: U15.21 U17.6 U18.6 | length 68.6
  Top Layer w0.2: U15.21@17.639,59.688 17.639,58.177 18.112,57.705 v1(18.15,57.705) ; v1(52.1,37.8) 52.316,37.584 56.604,37.584 56.765,37.423 v1(56.819,37.423) ; v1(55.973,32.055) 56.179,31.85 56.179,30.519 57.397,29.301 U18.6@57.959,29.301 ; v1(57.959,32.785) U17.6@57.959,33.445
  Bottom Layer w0.2: v1(18.15,57.705) 18.204,57.705 18.495,57.996 18.708,57.996 19.599,58.888 24.006,58.888 24.519,58.375 32.039,58.375 41.376,49.038 45.267,49.038 51.45,42.855 51.45,39.586 51.938,39.099 51.938,38.276 52.1,38.114 v1(52.1,37.8) ; v1(55.973,32.055) 56.284,31.744 56.284,30.954 57.06,30.178 57.082,30.178 57.119,30.141 57.584,30.141 58.459,31.015 58.459,32.285 v1(57.959,32.785) 57.959,36.283 v1(56.819,37.423)
UART_SNIFF4_RX: U18.1
UART_SNIFF4_TX: U17.1
UIM_CLK_7: C155.2 D15.C J8.12 SIM2.C3 | length 13.1
  Top Layer w0.2: J8.12@9.657,34.977 9.664,34.97 v1(9.664,33.589)
  Bottom Layer w0.2: v1(9.664,33.589) 10.83,34.754 SIM2.C3@10.83,41.965 10.83,42.617 11.4,43.187 C155.2@11.4,43.5 D15.C@12.5,43.5
UIM_DATA_7: C156.2 D16.C J8.10 SIM2.C7 | length 12.9
  Top Layer w0.2: J8.10@8.857,34.977 8.86,34.974 v1(8.86,33.584)
  Bottom Layer w0.2: v1(8.86,33.584) 8.86,33.986 9.56,34.686 SIM2.C7@9.56,41.965 9.501,42.024 9.501,42.781 9.2,43.082 C156.2@9.2,43.5 D16.C@10.3,43.5
UIM_PWR_7: C152.2 C153.2 D13.C J8.8 SIM2.C1 | length 16.4
  Top Layer w0.25: J8.8@8.057,34.977 8.057,35.972 8.386,36.301 11.193,36.301 v1(12.597,37.705)
  Bottom Layer w0.25: v1(12.597,37.705) 12.597,38.422 15.177,41.002 15.737,41.002 15.91,41.175 SIM2.C1@15.91,41.965 15.91,43.28 16.13,43.5 C152.2@16.5,43.5 C153.2@17.6,43.5 D13.C@18.7,43.5
UIM_RST_7: C154.2 D14.C J8.14 SIM2.C2 | length 14.4
  Top Layer w0.2: J8.14@10.457,34.977 10.457,33.877 10.685,33.649 v1(12.014,33.649)
  Bottom Layer w0.2: v1(12.014,33.649) 12.025,33.66 12.025,39.05 13.37,40.395 SIM2.C2@13.37,41.965 13.37,42.773 13.6,43.003 C154.2@13.6,43.5 D14.C@14.7,43.5
USB0_8_N: R102.2 U3.1 | length 9.5
  Top Layer w0.26: R102.2@33.63,33.801 33.63,34.216 33.905,34.491 33.905,34.977 37.178,38.25 U3.1@40.75,38.25
USB0_8_P: R99.2 U3.2 | length 8.8
  Top Layer w0.26: R99.2@34.59,33.801 34.59,34.186 34.315,34.461 34.315,34.807 37.258,37.75 U3.2@40.75,37.75
USB0_D_3_N: D7.2 J10.2 R97.1 USB0_DN.X | length 12.2
  Top Layer w0.26: J10.2@4.16,41.963 4.215,41.908 4.803,41.908 4.868,41.843 5.343,41.843 v1(6.372,42.872) 6.543,43.043 6.543,43.864 ; R97.1@4.905,48.005 4.905,47.805 6.54,46.17 6.54,45.009 6.54,44.669 6.543,44.665 6.543,43.864 ; D7.2@5.793,43.788 6.467,43.788 6.543,43.864
  Bottom Layer w0.26: v1(6.372,42.872) 6.398,42.898 6.398,43.398 USB0_DN.X@8,45
USB0_D_3_P: D7.3 J10.3 R98.1 USB0_DP.X | length 11.7
  Top Layer w0.26: J10.3@4.16,41.313 4.215,41.368 4.803,41.368 4.868,41.433 5.711,41.433 v1(6.589,42.311) 6.953,42.676 6.953,43.864 ; R98.1@5.785,48.005 5.785,47.505 6.95,46.34 6.95,45.252 6.952,45.25 6.952,44.842 6.953,44.84 6.953,44.835 ; 6.95,44.839 6.953,44.835 ; D7.3@7.703,43.788 7.03,43.788 6.953,43.864 ; 6.953,43.864 6.953,44.835
  Bottom Layer w0.26: v1(6.589,42.311) 6.593,42.315 7.315,42.315 USB0_DP.X@8,43
USB0_D_RES_3_N: R97.2 U15.44 | length 7
  Top Layer w0.26: R97.2@4.905,48.955 4.905,49.355 7.843,52.293 9.333,52.293 9.378,52.338 U15.44@10.289,52.338
USB0_D_RES_3_P: R98.2 U15.45 | length 6.1
  Top Layer w0.26: R98.2@5.785,48.955 5.785,49.539 5.781,49.543 5.781,49.651 8.012,51.883 9.333,51.883 9.378,51.838 U15.45@10.289,51.838
USB1_8_N: R104.2 U3.3 | length 7.3
  Top Layer w0.26: R104.2@35.568,33.801 35.577,33.801 35.721,33.945 35.721,34.417 35.842,34.539 35.842,35.16 37.892,37.21 40.235,37.21 40.265,37.24 40.74,37.24 U3.3@40.75,37.25
USB1_8_P: R103.2 U3.4 | length 6.6
  Top Layer w0.26: R103.2@36.527,33.801 36.518,33.801 36.374,33.945 36.374,34.417 36.252,34.539 36.252,34.991 38.062,36.8 40.225,36.8 40.265,36.76 40.74,36.76 U3.4@40.75,36.75
USB1_D_3_N: D8.2 J19.2 R100.2 USB1_DN.X | length 10.1
  Top Layer w0.26: J19.2@4.16,63.096 4.215,63.041 4.803,63.041 4.868,62.976 5.13,62.976 v1(5.2,63.046) 5.27,62.976 6.51,62.976 6.959,62.527 6.959,61.808 ; D8.2@7.703,61.838 6.989,61.838 6.959,61.808 ; R100.2@7.804,58.754 7.509,59.05 7.166,59.05 6.959,59.257 6.959,61.808
  Bottom Layer w0.26: USB1_DN.X@4,64 4,63.5 4.454,63.046 v1(5.2,63.046)
USB1_D_3_P: D8.3 J19.3 R101.2 USB1_DP.X | length 9.3
  Top Layer w0.26: J19.3@4.16,62.446 4.215,62.501 4.803,62.501 4.868,62.566 5.13,62.566 v1(5.2,62.496) 5.27,62.566 6.34,62.566 6.549,62.357 6.549,61.768 ; D8.3@5.793,61.838 6.479,61.838 6.549,61.768 ; R101.2@7.168,58.118 6.885,58.401 6.885,58.732 6.549,59.067 6.549,61.768
  Bottom Layer w0.26: USB1_DP.X@4,62 4.496,62.496 v1(5.2,62.496)
USB1_D_uC_3_N: R100.1 U15.35 | length 2.6
  Top Layer w0.26: R100.1@8.476,58.083 8.767,57.792 8.767,57.325 9.255,56.838 U15.35@10.289,56.838
USB1_D_uC_3_P: R101.1 U15.36 | length 2.9
  Top Layer w0.26: R101.1@7.84,57.446 8.208,57.078 8.372,57.078 9.112,56.338 U15.36@10.289,56.338
USB2_8_N: R31.2 U3.6 | length 1.4
  Top Layer w0.26: R31.2@39.425,36.001 39.569,35.856 39.83,35.856 39.936,35.75 U3.6@40.75,35.75
USB2_8_P: R30.2 U3.7 | length 1.4
  Top Layer w0.26: R30.2@39.425,35.059 39.569,35.204 40.004,35.204 40.05,35.25 U3.7@40.75,35.25
USB3_8_N: R108.2 U3.8 | length 4.1
  Top Layer w0.26: R108.2@37.802,32.921 37.811,32.921 37.953,33.064 37.953,33.733 38.398,34.177 39.598,34.177 40.17,34.75 U3.8@40.75,34.75
USB3_8_P: R107.2 U3.9 | length 3.3
  Top Layer w0.26: R107.2@38.756,32.913 38.747,32.913 38.674,32.986 38.611,33.049 38.611,33.318 38.55,33.379 38.55,33.615 38.702,33.767 39.767,33.767 40.25,34.25 U3.9@40.75,34.25
USB_EN2_1: HUB_EN2.X Q6.3 R20.2 R56.2 | length 84.8
  Top Layer w0.15: v1(37.4,50.45) 38.5,51.55 38.5,57.05 38.085,57.465 38.085,58.16 40.093,60.169 40.093,64.464 41.295,65.666 v1(41.708,65.666)
  Top Layer w0.2: v1(35.75,81.725) 37.65,83.625 37.65,84.583 37.767,84.7 R20.2@39.625,84.7 ; Q6.3@37.641,24.038 37.641,23.559 ; R56.2@37.666,22.938 37.641,22.963 37.641,23.559 ; v1(38.175,23.559) 37.641,23.559 ; v1(39.248,25.559) 39.248,27.546 40.438,28.736 v1(40.438,30.705)
  Bottom Layer w0.15: v1(35.75,81.725) 35.75,80.972 34.739,79.961 34.739,71.588 40.698,65.629 41.67,65.629 v1(41.708,65.666) ; v1(37.4,50.45) 33.324,50.45 31.425,48.551 31.425,45.587 30.354,44.517 30.354,37.572 35.927,32 38.403,32 38.899,31.504 39.638,31.504 v1(40.438,30.705)
  Bottom Layer w0.2: v1(38.175,23.559) 37.85,23.884 37.85,24.286 38,24.436 HUB_EN2.X@38,25 38.559,25.559 v1(39.248,25.559)
USB_FS.D_1_N: J1.28 U3.30 USB_FS_DN.X | length 37.5
  Top Layer w0.26: U3.30@44.5,39 44.51,39.01 44.51,39.616 45.194,40.3 46.18,40.3 47.01,41.13 47.781,41.901 50.402,41.901 52.004,40.299 55.201,40.299 59.19,36.31 59.19,24.89 57.69,23.39 v1@57.69,20.4 ; 57.199,19.11 57.199,19.599 57.69,20.09 v1@57.69,20.4 ; v1(57.62,20.4) v1@57.69,20.4
  Bottom Layer w0.26: USB_FS_DN.X@57,21 57.6,20.4 v1(57.62,20.4)
USB_FS.D_1_P: J1.26 U3.31 USB_FS_DP.X | length 38.9
  Top Layer w0.26: U3.31@44,39 44,39.686 45.024,40.71 46.01,40.71 46.6,41.3 47.611,42.311 50.572,42.311 52.174,40.709 55.371,40.709 59.6,36.48 59.6,24.72 58.1,23.22 v1@58.1,20.33 ; 57.625,19.098 57.625,19.445 58.1,19.92 v1@58.1,20.33 ; v1(58.17,20.4) v1@58.1,20.33
  Bottom Layer w0.26: v1(58.17,20.4) USB_FS_DP.X@58.77,21
USB_FS.ID_1: J1.30 USB_FS_ID.X | length 3.4
  Top Layer w0.2: v1(56.6,19.8) 56.81,19.59 J1.30@56.81,18.685
  Bottom Layer w0.2: USB_FS_ID.X@55,21 55,20.856 56.056,19.8 v1(56.6,19.8)
USB_FS.VBUS_1: J1.24 USB_FS_VBUS.X | length 4.2
  Top Layer w0.2: J1.24@58.01,18.685 58.01,19.184 58.726,19.9 59.9,19.9 v1(60.4,20.4)
  Bottom Layer w0.2: v1(60.4,20.4) USB_FS_VBUS.X@61,21
USB_H0.D_1_N: D5.3 J15.2 R102.1 USB_H0_DN.X | length 25.1
  Top Layer w0.26: D5.3@31.345,18.7 32.093,18.7 ; J15.2@32.8,13.71 32.805,13.71 33.595,14.5 33.595,14.608 32.093,16.11 32.093,18.7 ; R102.1@33.63,32.851 33.63,32.494 33.905,32.219 33.905,30.37 v1(33.835,30.3) 33.905,30.23 33.905,25.041 32.093,23.229 32.093,18.7
  Bottom Layer w0.2: USB_H0_DN.X@31,29 31.7,29 32.445,29.745 32.684,29.745 32.689,29.75 33.265,29.75 33.815,30.3 v1(33.835,30.3)
USB_H0.D_1_P: D5.2 J15.3 R99.1 USB_H0_DP.X | length 23.8
  Top Layer w0.26: D5.2@33.255,18.7 32.503,18.7 ; R99.1@34.59,32.851 34.59,32.494 34.315,32.219 34.315,30.37 v1(34.385,30.3) 34.315,30.23 34.315,24.872 32.503,23.059 32.503,18.7 ; J15.3@34.8,13.71 34.795,13.71 34.005,14.5 34.005,14.778 32.503,16.28 32.503,18.7
  Bottom Layer w0.2: USB_H0_DP.X@33,29 33.244,29 33.721,29.476 34.385,30.141 v1(34.385,30.3)
USB_H1.D_1_N: D6.3 J15.6 R104.1 USB_H1_DN.X | length 25.6
  Top Layer w0.26: J15.6@32.8,11.09 32.942,11.09 33.595,11.743 33.595,12.02 34.175,12.6 35.53,12.6 35.843,12.913 35.843,18.7 ; D6.3@35.095,18.7 35.843,18.7 ; R104.1@35.568,32.851 35.568,32.351 35.843,32.076 35.843,31.906 35.843,29.07 v1(35.773,29) 35.843,28.93 35.843,18.7
  Bottom Layer w0.26: USB_H1_DN.X@35,29 v1(35.773,29)
USB_H1.D_1_P: D6.2 J15.7 R103.1 USB_H1_DP.X | length 25.5
  Top Layer w0.26: J15.7@34.8,11.09 34.658,11.09 34.005,11.743 34.005,11.851 34.345,12.19 35.7,12.19 36.253,12.743 36.253,18.7 ; R103.1@36.527,32.851 36.527,32.351 36.252,32.076 36.253,31.736 36.252,29.07 v1(36.323,29) 36.253,28.93 36.253,18.7 ; D6.2@37.005,18.7 36.253,18.7
  Bottom Layer w0.26: v1(36.323,29) USB_H1_DP.X@37,29
USB_H2.D_1_N: R5.2 R31.1 USB_H2_DN.X | length 41.6
  Top Layer w0.26: v1(32.33,40.627) 32.629,40.926 32.629,46.794 34.621,48.786 34.621,57.967 36.465,59.811 36.465,65.897 36.3,66.062 v1(36.3,66.1) 36.3,66.461 36.12,66.641 R5.2@36.12,67.025 ; v1(37.399,34.999) 37.399,35.037 37.794,35.432 37.794,35.729 38.075,36.01 R31.1@38.475,36.01
  Bottom Layer w0.26: v1(32.33,40.627) 32.651,40.948 33.378,40.948 33.919,40.408 33.919,37.419 36.433,34.904 36.999,34.904 37.048,34.953 37.353,34.953 v1(37.399,34.999) ; v1(36.3,66.1) 36.78,66.58 37.42,66.58 USB_H2_DN.X@38,66
USB_H2.D_1_P: R4.2 R30.1 USB_H2_DP.X | length 41.6
  Top Layer w0.26: v1(32.719,40.238) 33.039,40.558 33.039,46.624 35.031,48.616 35.031,57.797 36.875,59.641 36.875,65.897 37.04,66.062 v1(37.04,66.1) 37.04,66.465 37.22,66.645 R4.2@37.22,67.025 ; v1(37.399,34.399) 37.437,34.399 37.557,34.519 37.619,34.519 38.15,35.05 R30.1@38.475,35.05
  Bottom Layer w0.26: v1(32.719,40.238) 33.019,40.538 33.209,40.538 33.509,40.238 33.509,37.249 36.264,34.494 36.999,34.494 37.048,34.445 37.353,34.445 v1(37.399,34.399) ; v1(37.04,66.1) 37.04,64.96 USB_H2_DP.X@38,64
USB_H3.D_1_N: J8.36 R108.1 USB_H3_DN.X | length 22.8
  Top Layer w0.26: J8.36@22.457,34.977 22.535,34.899 22.535,33.847 22.652,33.73 22.652,33.417 23.186,32.883 24.449,32.883 24.451,32.881 26.289,32.881 26.405,32.765 v1(26.47,32.765) ; R108.1@37.802,31.971 37.802,31.587 38.052,31.337 38.052,30.348 v1(38.4,30)
  Bottom Layer w0.26: v1(26.47,32.765) 26.717,32.765 26.763,32.811 26.794,32.811 26.843,32.86 33.534,32.86 35.441,30.952 37.448,30.952 v1(38.4,30) 38.9,30 39.2,29.7 39.2,29.4 39,29.2 USB_H3_DN.X@39,29
USB_H3.D_1_P: J8.38 R107.1 USB_H3_DP.X | length 23
  Top Layer w0.26: J8.38@23.257,34.977 23.179,34.899 23.179,33.847 23.062,33.73 23.062,33.587 23.356,33.293 24.619,33.293 24.621,33.291 26.271,33.291 26.3,33.319 26.424,33.319 v1(26.47,33.365) ; v1(38.748,30.552) 38.462,30.838 38.462,31.253 38.756,31.547 R107.1@38.756,31.963
  Bottom Layer w0.26: v1(26.47,33.365) 26.717,33.365 26.763,33.319 26.794,33.319 26.843,33.27 33.704,33.27 35.611,31.362 37.938,31.362 v1(38.748,30.552) 38.8,30.5 39.1,30.5 40.6,29 USB_H3_DP.X@41,29
USB_OC0_1: U3.13 U7.10 | length 18.4
  Top Layer w0.2: v1(42.939,32.438) 42.939,32.492 43,32.553 U3.13@43,33.5 ; U7.10@47.339,21.363 47.339,21.062 47.456,20.945 47.622,20.945 48.259,21.582 48.259,24.664 49.266,25.671 v1(49.266,25.722)
  Bottom Layer w0.2: v1(42.939,32.438) 44.839,32.438 45.739,31.538 47.126,31.538 47.883,30.781 48.539,30.124 48.539,28.838 49.266,28.111 v1(49.266,25.722)
USB_OC1_1: U3.17 U7.6 | length 15.5
  Top Layer w0.2: v1(44.378,26.971) 44.378,27.025 44.303,27.101 44.303,28.401 46.125,30.223 46.125,31.686 45,32.81 U3.17@45,33.5 ; v1(44.839,24.138) 44.664,23.963 44.664,21.112 44.888,20.888 45.189,20.888 45.339,21.038 U7.6@45.339,21.363
  Bottom Layer w0.2: v1(44.378,26.971) 44.387,26.971 45.339,26.018 45.339,24.53 44.985,24.176 44.877,24.176 v1(44.839,24.138)
USB_R_5_N: R5.1 U1.28 | length 8.8
  Top Layer w0.26: R5.1@36.12,67.982 36.12,68.355 36.465,68.7 36.465,69.243 37.961,70.738 37.961,73.125 38.966,74.13 40.03,74.13 U1.28@40.3,74.4
USB_R_5_P: R4.1 U1.29 | length 8
  Top Layer w0.26: R4.1@37.22,67.982 37.22,68.355 36.875,68.7 36.875,69.073 38.371,70.569 38.371,72.955 38.986,73.57 40.03,73.57 U1.29@40.3,73.3
VBAT_12: BAT.X J16.1 J16.2 U11.13 U11.14 | length 19.1
  Top Layer w0.3: U11.13@94.255,38.93 v1@95.67,38.93 ; U11.14@94.255,39.43 95.17,39.43 v1@95.67,38.93 ; v1(95.7,38.9) v1@95.67,38.93
  Top Layer w2.5: J16.1@92.1,14.343 J16.2@92.1,30.343
  other v1: 95.7,38.1 96.6,38.1 96.6,38.9
VDD_TCX0_6: LORA_VDD_TCX0.X R12.1 R86.2 U23.48 | length 9.1
  Top Layer w0.2: v1(9.05,75.731) U23.48@9.05,78.6 ; R86.2@9.591,74.09 v1(9.591,73.49) 10.491,73.49 10.624,73.623 R12.1@10.624,74.09
  Bottom Layer w0.2: v1(9.05,75.731) 9.05,74.031 v1(9.591,73.49) 10.49,73.49 LORA_VDD_TCX0.X@11,74
VIN: J1.21 J1.32 J1.41 J1.48 R92.2 | length 12
  Top Layer w0.2: J1.48@53.21,18.685 53.21,18.235 53.446,17.999 53.862,17.999 54.21,17.651 54.41,17.651 ; J1.41@54.41,15.605 54.41,17.651 ; J1.32@56.41,18.685 56.41,18 56.401,17.991 ; v1(57.436,17.991) 56.401,17.991 ; J1.21@58.41,15.605 v1(58.41,16.218) ; 54.41,17.651 54.751,17.651 55.091,17.991 56.401,17.991
  Top Layer w0.5: v1(65.725,19.61) 65.725,19.386 65.939,19.172 65.939,18.934 66.183,18.689 R92.2@66.422,18.689 ; v1(66.425,19.61) 66.425,18.692 R92.2@66.422,18.689 ; v1(67.125,19.61) 67.125,19.392 66.905,19.172 66.905,18.934 66.661,18.689 R92.2@66.422,18.689
VSYS: J1.53 J1.64 | length 3.9
  Top Layer w0.2: J1.64@50.01,18.685 50.01,18.079 51.032,17.057 52.01,16.079 J1.53@52.01,15.605
Y_13: J6.3 U4.4 Y.X | length 17.7
  Top Layer w0.2: U4.4@79.725,16.35 82.25,16.35 85.5,13.1 88.2,13.1 90.1,11.2 90.1,9.05 J6.3@90.31,8.84
  Bottom Layer w0.2: Y.X@89,11 90.277,9.723 90.277,8.873 J6.3@90.31,8.84
Z_13: J6.2 U4.3 Z.X | length 24.1
  Top Layer w0.2: U4.3@79.725,15.85 82.05,15.85 85.4,12.5 87.7,12.5 89.3,10.9 89.3,8.33 J6.2@91.33,6.3
  Bottom Layer w0.2: Z.X@87,11 87.869,10.131 88.784,10.131 89.3,9.615 89.3,8.33 J6.2@91.33,6.3
pads on no net: CN1.7 CN2.6 CN2.7 CN2.8 CN3.6 CN3.7 CN3.8 Fiducial_1.1 Fiducial_2.1 Fiducial_3.1 J1.2 J1.4 J1.6 J1.8 J1.10 J1.12 J1.14 J1.16 J1.18 J1.20 J1.23 J1.25 J1.27 J1.29 J4.21 J4.22 J4.23 J4.24 J4.25 J4.26 J4.27 J4.28 J4.29 J4.30 J4.31 J4.32 J4.33 J4.34 J4.35 J4.36 J4.37 J4.38 J4.39 J4.40 J6.MH1 J6.MH2 J7.MH1 J7.MH2 J8.1 J8.3 J8.5 J8.6 J8.16 J8.17 J8.19 J8.24 J8.28 J8.37 J8.42 J8.43 J8.44 J8.45 J8.46 J8.47 J8.48 J8.49 J8.51 J8.MH1 J8.MH2 J8.MP1 J8.MP2 J10.4 J12.MH1 J12.MH2 J13.4 J13.MH1 J13.MH2 J14.4 J14.MH1 J14.MH2 J17.17 J17.SHNP1 J17.SHNP2 J19.4 PB2.PAD Q4.NC SIM1.C6 SIM2.C6 U1.2 U1.6 U1.8 U1.19 U1.23 U1.24 U1.25 U1.26 U1.27 U1.31 U1.34 U1.35 U1.36 U1.37 U1.44 U1.45 U1.46 U1.47 U1.48 U1.49 U2.21 U2.22 U2.29 U2.30 U3.11 U3.19 U3.20 U3.21 U3.28 U4.1 U4.5 U4.8 U4.9 U4.16 U4.23 U4.24 U6.3 U11.2 U11.3 U12.4 U13.14 U14.4 U15.2 U15.6 U15.9 U15.14 U15.16 U15.22 U15.23 U15.24 U15.26 U15.27 U15.33 U15.37 U15.50 U15.51 U15.53 U15.55 U15.56 U15.62 U23.2 U23.8 U23.9 U23.11 U23.12 U23.13 U23.14 U23.15 U23.16 U23.17 U23.18 U23.19 U23.20 U23.28 U23.29 U23.30 U23.31 U23.33 U23.35 U23.36 U23.37 U23.40 U23.45 U24.3 U24.10 U25.3 U25.10 X1.3 Y1.2 Y1.4

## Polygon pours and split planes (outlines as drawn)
GND on Top Layer "GND_TOP" (solid, remove dead copper, pour order 87): 0,102.2 78.2,102.2 78.2,79.4 85.1,79.4 88.439,83.481 88.439,88.089 89.726,89.376 91.483,89.376 91.483,94.1 101.6,94.1 101.6,0 0,0
GND on Top Layer "RF_COPLANAR" (solid, pour order 36): 11.52,98.843 11.52,92.98 15.45,89.05 15.45,87.15 19.7,87.15 19.7,89.8 15.15,94.35 15.15,98.843
GND on Top Layer "RF_COPLANAR" (solid, pour order 35): 64.95,70.74 66.64,70.74 ccw(c66.64,73) 68.9,73 68.9,80.3 76.5,87.9 76.5,98.9 72.4,98.9 72.4,93.9 69.1,90.6 69.1,89.1 67.924,87.924 67.924,87.224 63.45,82.75 63.45,70.723 63.462,70.712
+5V on Top Layer "+5V_L01_P033" (solid, remove dead copper, pour order 33): 15.1,39.441 16.3,39.441 16.3,40.1 15.895,40.505 16.3,41.41 15.1,41.41 15.505,40.505 15.1,40.1
+3V8 on Top Layer "+3V8_L01_P073" (solid, remove dead copper, pour order 73): 61.435,64.15 61.435,67.596 65.445,67.596 66.55,67.596 66.55,65.5 64.5,65.5 63.15,64.15
GND on Top Layer "RF_COPLANAR" (solid, pour order 39): 14.36,96.003 14.333,96.003 ccw(c14.333,95.225) 13.555,95.269 13.554,95.225 13.116,95.222 13.114,95.266 ccw(c12.334,95.222) 12.334,96.003 12.311,96.003 12.311,96.55 14.36,96.55
PWR_IN_12 on Top Layer "PWR_IN" (solid, pour order 79): 83.979,83.69 87.468,83.69 87.827,84.049 87.827,88.728 88.971,89.872 90.334,89.872 90.712,90.25 90.712,91.75 85.147,91.75 83.979,90.582
GND on Top Layer "GND_L01_P048" (solid, pour order 48): 77,59.806 77,62 74.2,62 74.2,59.795
GND on Top Layer "GND_L01_P041" (solid, pour order 41): 74.2,66.586 74.2,65 77,65 77,66.597
+5V on Top Layer "+5V_L01_P040" (solid, pour order 40): 73.282,33.607 71.907,33.607 71.59,33.29 71.59,32.885 70.962,32.885 70.962,34.147 71.159,34.343 73.282,34.343
+3V3 on Top Layer "+3V3_L01_P080" (solid, pour order 80): 12.8,77.756 12.8,76.6 12.565,76.365 12.565,74.591 12.711,74.445 13.88,74.445 14.12,74.685 16.988,74.685 17.09,74.786 17.09,75.71 16.3,76.5 14.522,76.5 14.095,76.892 14.095,77.756
GND on Top Layer "GND_L01_P089" (solid, pour order 89): 75.447,92.5 78.2,90.706 83.458,90.706 84.949,92.198 102.323,92.198 102.3,101.7 75.447,101.7
GND on POWER "GND_L03_P086" (solid, remove dead copper, pour order 86): 0,101.75 0,0 103.75,0 102,1.75 102,101.998
+3V3 on POWER "+3V3_L03_P085" (solid, remove dead copper, pour order 85): 0.25,90.5 2,92.25 9.351,92.25 10.2,91.401 10.2,90.25 8.648,88.822 8.648,78.617 9.862,77 17.6,77 20.25,73.5 20.25,68.253 21.66,66.768 35.954,66.768 36.913,65.55 101.6,65.55 101.6,0 1,0 0,1
GND on POWER "GND_L03_P031" (solid, remove dead copper, pour order 31): 7.6,25.496 12.736,25.506 13.28,26 42.19,26 44.4,26 51.596,18.804 65,18.804 65,7.732 45.966,7.732 43.187,4.953 16.329,4.999 11.654,13.181 8.819,13.181 7.6,14.4
+3V3A on POWER "+3V3A_L03_P069" (solid, remove dead copper, pour order 69): 39.5,33.25 39.65,33.1 41.25,33.1 41.25,37.75 41.85,38.35 45.27,38.35 46.08,39.25 47.1,39.25 47.1,40.15 40.713,40.15 39.5,38.937
GND on POWER "GND_L03_P014" (solid, remove dead copper, pour order 14): 32.1,41.6 27.213,41.6 27.213,36.709 24.914,34.414 24.914,30.286 26.5,28.7 39.2,28.7 41.353,28.7 41.353,31.8 39.6,31.8 39,32.5 38.939,35.297 34.8,38.581 34.8,40.9 34.1,41.6
VIN on POWER "VIN_L03_P022" (solid, remove dead copper, pour order 22): 57,16 65,16 65,19 67.4,19 67.4,20.555 60.555,20.555 59,19 57,19
GND on POWER "GND_L03_P010" (solid, remove dead copper, pour order 10): 63.894,55.939 59.569,59.895 46.595,59.895 41.975,55.275 41.975,52.202 46.298,52.202 55.5,43 55.5,41.5 58,39 78.215,39 79.464,40.249 79.464,53.536 77.061,55.939
GND on Bottom Layer "GND_BOT" (solid, remove dead copper, pour order 88): 0,101.473 0.152,101.625 101.473,101.625 101.473,0.102 101.575,0 0,0
+5V on Bottom Layer "+5V_L04_P056" (solid, pour order 56): 20.669,43.026 20.669,41.347 20.1,40.5 15.172,40.5 15.011,40.339 15.011,39.061 18.025,39.061 19.813,39.061 21.97,39.061 22.675,39.767 22.675,43.026
+3V3_PCIE on Bottom Layer "3V3_PCIE" (solid, pour order 55): 22.25,37.5 27.5,37.5 27.75,37.75 27.75,38.5 26.25,40 25.25,40 24.5,39.25 22.25,39.25
+5V on Bottom Layer "5V" (solid, pour order 64): 81.038,67.022 81.038,66.048 82.1,65.2 81.059,63.748 80.149,63.748 77.98,65.916 77.98,67.022
VBAT_12 on Bottom Layer "VBAT_12_L04_P083" (solid, remove dead copper, pour order 83): 95.3,39.3 95.3,33.41 94.35,32.46 91.786,32.463 90,30.677 90,29.8 91.577,28.223 94.791,28.223 97,30.432 97,39.3
GND on GND "GND_L02_P006" (solid, remove dead copper, pour order 6): 0,101.95 0,1 1,0 100,0 102,2 102,101 101,102

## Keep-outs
Top Layer:
  rectangle: 23.1,40.315 24.8,42.715
  region: 45.5,42.852 45.5,18.685 64.67,18.685 64.67,42.804
Keep-Out Layer:
  circle w0.254: c98.3,7.2 r2.288
  circle w0.254: c3.3,7.2 r3
  circle w0.254: c98.3,97.6 r3
  circle w0.254: c3.3,97.6 r3

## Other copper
Top Layer:
  rectangle net +5V: 85.533,64.52 88,66.7
  rectangle net +5V: 85.533,59.52 87.023,60.888
  region net NetC17_2: 12.31,96.003 12.364,96.003 cw(c12.364,95.254) 13.113,95.254 13.113,95.255 cw(c14.306,95.255) 14.306,96.003 14.36,96.003 ccw(c14.109,96.003) 14.109,96.254 13.113,96.254
  region net NetC9_2: 73.397,95.749 73.451,95.749 cw(c73.451,95) 74.2,95 74.2,95.001 cw(c75.393,95.001) 75.393,95.749 75.447,95.749 ccw(c75.196,95.749) 75.196,96 74.2,96
  pour cut-out: 7.59,24.29 31.59,24.29 34.59,27.29 34.59,34.29 38.59,38.29 38.59,39.29 48.59,49.29 48.59,58.29 49.59,59.29 49.59,63.29 43.909,63.29 38.59,68.609 38.59,72.029 39.565,72.883 41.239,72.883 41.239,74.819 39.565,74.819 38.898,75.773 33.855,75.773 33.59,75.508 33.59,67.029 31.59,67.029 31.59,65.057 32.392,64.255 32.469,47.66 32.47,47.305 31.956,46.79 31.956,42.284 28.962,39.29 23.59,39.29 17.59,33.29 10.59,33.29 7.59,30.29
  region net +5V_BQ: 85.484,64.147 87.712,64.147 89,62.859 89,44.61 90.038,43.572 88.584,43.572 87.712,44.444 87.712,61.344 85.484,63.554
  pour cut-out: 101.845,10 96.255,10 94.2,7.945 94.2,0 101.845,0
  region net +5V_MPM: 80.519,60.988 80.519,58.888 80.645,58.762 82.317,58.762 82.519,58.964 82.519,59.888 81.119,61.288
  region net +5V_MPM: 85.538,59.146 86.813,59.146 87.323,58.636 87.323,44.179 88.558,42.944 89.727,42.944 90.187,42.484 90.187,42.15 86.809,42.15 85.538,43.42
  pour cut-out: 41.595,34.338 37.305,30.048 37.305,10.048 36.005,8.748 29.185,8.748 27.995,9.938 27.995,22.205 26.075,24.338 30.595,28.858 30.595,35.338 34.595,39.338 41.595,39.338
  region net VBAT_12: 94.828,39.297 94.828,39.577 95.108,39.577 95.303,39.297 96.997,39.297 96.997,37.774 95.526,37.774 94.828,38.472
  region net SW_bq_12: 92.7,43 92.7,43.111 92.911,43.321 93.748,43.321 93.748,43.963 94.5,44.5 94.5,45.678 94.713,45.891 95.758,45.891 95.992,45.657 95.992,43.505 95.005,43.505 94.5,43 93.7,43
  region net +3V8: 98.2,44 98.2,41.67 97.521,40.992 95.487,40.992 95.076,40.58 94.794,40.58 94.794,39.78 95.076,39.78 95.619,39.78 95.635,39.765 98.326,39.765 99.7,41.139 99.7,44.7 98.2,44.7
  pour cut-out: 24.546,75.706 24.546,79.647 29.399,84.5 33.525,84.5 33.525,82.044 32.824,81.343 32.824,75.735
  pour cut-out: 95.432,43.368 93.773,41.727 93.749,40.722 94.827,40.728 95.166,41.14 96.589,41.122 97.982,42.514 97.9,43.353 97.9,46.2 96.3,46.2 96.298,43.363
  pour cut-out: 6.6,101.145 6.6,96.055 4.6,94.055 0,94.055 0,101.145
  pour cut-out: 94.62,101.514 94.62,96.435 97,94.055 101.6,94.055 101.6,101.514
  pour cut-out: 6.6,0 6.6,8.745 4.6,10.745 0,10.745 0,0
GND:
  pour cut-out: 101.845,10 96.255,10 94.2,7.945 94.2,0 101.845,0
  pour cut-out: 95,101.145 95,96.055 97,94.055 101.6,94.055 101.6,101.145
  pour cut-out: 94.62,101.514 94.62,96.435 97,94.055 101.6,94.055 101.6,101.514
  pour cut-out: 6.731,101.145 6.731,96.186 4.6,94.055 0,94.055 0,101.145
  pour cut-out: 6.6,0 6.6,8.745 4.6,10.745 0,10.745 0,0
  pour cut-out: 6.6,101.145 6.6,96.055 4.6,94.055 0,94.055 0,101.145
  pour cut-out: 95,101.145 95,96.055 97,94.055 101.6,94.055 101.6,101.145
POWER:
  pour cut-out: 101.845,10 96.255,10 94.2,7.945 94.2,0 101.845,0
  pour cut-out: 95,101.145 95,96.055 97,94.055 101.6,94.055 101.6,101.145
  pour cut-out: 94.62,101.514 94.62,96.435 97,94.055 101.6,94.055 101.6,101.514
  pour cut-out: 6.6,0 6.6,8.745 4.6,10.745 0,10.745 0,0
  pour cut-out: 6.731,101.145 6.731,96.186 4.6,94.055 0,94.055 0,101.145
Bottom Layer:
  rectangle net PWR_IN_12: 82.32,88.346 88.019,89.746
  pour cut-out: 27.429,39.407 29.1,39.407 30.984,41.29 33.59,41.29 34.59,40.29 34.59,37.29 35.285,36.595 38.749,36.595 39.692,35.651 39.692,30.735 33.59,31.29
  pour cut-out: 101.845,10 96.255,10 94.2,7.945 94.2,0 101.845,0
  pour cut-out: 95,101.145 95,96.055 97,94.055 101.6,94.055 101.6,101.145
  pour cut-out: 94.62,101.514 94.62,96.435 97,94.055 101.6,94.055 101.6,101.514
  region net +3V8: 63.4,67.5 63.4,65.9 68.5,65.9 68.5,67.5
  pour cut-out: 78.975,35.625 78.975,31.67 76.305,29 73.72,29 72.08,27.36 63.249,27.36 60.379,24.49 60.379,22.29 78.59,22.29 78.59,24.596 81.932,27.938 81.932,35.648
  pour cut-out: 55.59,64.29 57.59,62.29 71.411,62.29 82.59,51.111 82.59,35.29 52.59,35.29 52.59,45.29 44.59,53.29 44.59,56.29 46.59,58.29 48.59,58.29 48.59,64.29
  pour cut-out: 0,24.29 0,26.79 0,29.386 0.598,28.788 5.563,28.788 8.392,26.3 47.839,26.3 52.09,21.79 79.59,21.79 79.59,0 0.164,0 0.164,6.271
  pour cut-out: 52.45,36.29 52.45,29.29 61.59,29.29 63.095,30.795 68.526,30.795 70.643,32.913 70.643,36.237 70.59,36.29
  pour cut-out: 6.731,101.145 6.731,96.186 4.6,94.055 0,94.055 0,101.145
  pour cut-out: 24.075,67.387 28.952,67.387 31.792,67.387 34.044,65.134 39.107,65.134 42.245,61.85 45.971,61.85 47.321,63.2 49.447,63.2 49.447,59.147 44.739,54.439 44.739,51.6 39.915,51.6 28.559,62.918 24.168,64.717
  pour cut-out: 24.088,28.6 24.088,37.214 27.585,37.214 28.5,38.161 31.439,38.161 37.373,32.226 38.068,32.226 39.688,30.606 39.688,29.091 39.197,28.6 35.914,28.6
  pour cut-out: 77.59,11.29 78.59,11.29 86.59,3.29 94.59,3.29 94.59,0.29 77.59,0.29
  pour cut-out: 79.59,20.29 79.59,24.29 76.59,24.29 75.59,23.29 75.59,20.29

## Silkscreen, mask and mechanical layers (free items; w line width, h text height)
Top Overlay:
  drawing of 195 lines, arcs and shapes, not listed
Bottom Overlay:
  drawing of 579 lines, arcs and shapes, not listed
Top Solder:
  drawing of 6 lines, arcs and shapes, not listed
Bottom Solder:
  drawing of 10 lines, arcs and shapes, not listed
Route Tool Path:
  lines w2: -1,4.953 -1,16 ; -1,5 ccw(c5,5) 5,-1 96.647,-1 ccw(c96.647,4.953) 102.6,4.953 102.6,16 ; -1,19.2 -1,84 ; -1,87.2 -1,96.6 cw(c5,96.6) 5,102.6 96.6,102.6 cw(c96.6,96.6) 102.6,96.6 102.6,87.2 ; 102.6,19.2 102.6,84
Board:
  lines w0.1: 4.978,101.605 96.627,101.605 cw(c96.627,96.627) 101.605,96.627 101.605,4.978 cw(c96.627,4.978) 96.627,0.001 4.978,0.001 cw(c4.978,4.978) 0,4.978 ; 4.978,101.606 ccw(c4.978,96.628) 0.001,96.628 0.001,4.979 ; 0,4.978 0.001,4.979
Foratura:
  drawing of 639 lines, arcs and shapes, not listed
  text "3.2mm" at 3.8,95.3 h0.5
  text "3.2mm" at 98.8,95.3 h0.5
  text "3.2mm" at 3.9,9.1 h0.5
  text "3.2mm" at 98.9,9.1 h0.5

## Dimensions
101.6,101.6 to 101.6,0 on Scoring
0,101.6 to 101.6,101.6 on Scoring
